            <field>
              <name>SETENA11</name>
              <description>serial peripheral interface 1 interrupt set-enable bit</description>
              <bitOffset>11</bitOffset>
              <bitWidth>1</bitWidth>
              <access>read-write</access>
              <enumeratedValues>
                <enumeratedValue>
                  <name>0</name>
                  <description>write: no effect; read: serial peripheral interface 1 interrupt disabled</description>
                  <value>#0</value>
                </enumeratedValue>
                <enumeratedValue>
                  <name>1</name>
                  <description>write: enable serial peripheral interface 1 interrupt; read: serial peripheral interface 1 interrupt enabled</description>
                  <value>#1</value>
                </enumeratedValue>
              </enumeratedValues>
            </field>
            <field>
              <name>SETENA12</name>
              <description>UART0 status and error interrupt set-enable bit</description>
              <bitOffset>12</bitOffset>
              <bitWidth>1</bitWidth>
              <access>read-write</access>
              <enumeratedValues>
                <enumeratedValue>
                  <name>0</name>
                  <description>write: no effect; read: UART0 status and error interrupt disabled</description>
                  <value>#0</value>
                </enumeratedValue>
                <enumeratedValue>
                  <name>1</name>
                  <description>write: enable UART0 status and error interrupt; read: UART0 status and error interrupt enabled</description>
                  <value>#1</value>
                </enumeratedValue>
              </enumeratedValues>
            </field>
            <field>
              <name>SETENA13</name>
              <description>UART1 status and error interrupt set-enable bit</description>
              <bitOffset>13</bitOffset>
              <bitWidth>1</bitWidth>
              <access>read-write</access>
              <enumeratedValues>
                <enumeratedValue>
                  <name>0</name>
                  <description>write: no effect; read: UART1 status and error interrupt disabled</description>
                  <value>#0</value>
                </enumeratedValue>
                <enumeratedValue>
                  <name>1</name>
                  <description>write: enable UART1 status and error interrupt; read: UART1 status and error interrupt enabled</description>
                  <value>#1</value>
                </enumeratedValue>
              </enumeratedValues>
            </field>
            <field>
              <name>SETENA14</name>
              <description>UART2 status and error interrupt set-enable bit</description>
              <bitOffset>14</bitOffset>
              <bitWidth>1</bitWidth>
              <access>read-write</access>
              <enumeratedValues>
                <enumeratedValue>
                  <name>0</name>
                  <description>write: no effect; read: UART2 status and error interrupt disabled</description>
                  <value>#0</value>
                </enumeratedValue>
                <enumeratedValue>
                  <name>1</name>
                  <description>write: enable UART2 status and error interrupt; read: UART2 status and error interrupt enabled</description>
                  <value>#1</value>
                </enumeratedValue>
              </enumeratedValues>
            </field>
            <field>
              <name>SETENA15</name>
              <description>Analog-to-digital converter 0 interrupt set-enable bit</description>
              <bitOffset>15</bitOffset>
              <bitWidth>1</bitWidth>
              <access>read-write</access>
              <enumeratedValues>
                <enumeratedValue>
                  <name>0</name>
                  <description>write: no effect; read: Analog-to-digital converter 0 interrupt disabled</description>
                  <value>#0</value>
                </enumeratedValue>
                <enumeratedValue>
                  <name>1</name>
                  <description>write: enable Analog-to-digital converter 0 interrupt; read: Analog-to-digital converter 0 interrupt enabled</description>
                  <value>#1</value>
                </enumeratedValue>
              </enumeratedValues>
            </field>
            <field>
              <name>SETENA16</name>
              <description>Comparator 0 interrupt set-enable bit</description>
              <bitOffset>16</bitOffset>
              <bitWidth>1</bitWidth>
              <access>read-write</access>
              <enumeratedValues>
                <enumeratedValue>
                  <name>0</name>
                  <description>write: no effect; read: Comparator 0 interrupt disabled</description>
                  <value>#0</value>
                </enumeratedValue>
                <enumeratedValue>
                  <name>1</name>
                  <description>write: enable Comparator 0 interrupt; read: Comparator 0 interrupt enabled</description>
                  <value>#1</value>
                </enumeratedValue>
              </enumeratedValues>
            </field>
            <field>
              <name>SETENA17</name>
              <description>Timer PWM module 0 interrupt set-enable bit</description>
              <bitOffset>17</bitOffset>
              <bitWidth>1</bitWidth>
              <access>read-write</access>
              <enumeratedValues>
                <enumeratedValue>
                  <name>0</name>
                  <description>write: no effect; read: Timer PWM module 0 interrupt disabled</description>
                  <value>#0</value>
                </enumeratedValue>
                <enumeratedValue>
                  <name>1</name>
                  <description>write: enable Timer PWM module 0 interrupt; read: Timer PWM module 0 interrupt enabled</description>
                  <value>#1</value>
                </enumeratedValue>
              </enumeratedValues>
            </field>
            <field>
              <name>SETENA18</name>
              <description>Timer PWM module 1 interrupt set-enable bit</description>
              <bitOffset>18</bitOffset>
              <bitWidth>1</bitWidth>
              <access>read-write</access>
              <enumeratedValues>
                <enumeratedValue>
                  <name>0</name>
                  <description>write: no effect; read: Timer PWM module 1 interrupt disabled</description>
                  <value>#0</value>
                </enumeratedValue>
                <enumeratedValue>
                  <name>1</name>
                  <description>write: enable Timer PWM module 1 interrupt; read: Timer PWM module 1 interrupt enabled</description>
                  <value>#1</value>
                </enumeratedValue>
              </enumeratedValues>
            </field>
            <field>
              <name>SETENA19</name>
              <description>Timer PWM module 2 interrupt set-enable bit</description>
              <bitOffset>19</bitOffset>
              <bitWidth>1</bitWidth>
              <access>read-write</access>
              <enumeratedValues>
                <enumeratedValue>
                  <name>0</name>
                  <description>write: no effect; read: Timer PWM module 2 interrupt disabled</description>
                  <value>#0</value>
                </enumeratedValue>
                <enumeratedValue>
                  <name>1</name>
                  <description>write: enable Timer PWM module 2 interrupt; read: Timer PWM module 2 interrupt enabled</description>
                  <value>#1</value>
                </enumeratedValue>
              </enumeratedValues>
            </field>
            <field>
              <name>SETENA20</name>
              <description>real time clock alarm interrupt set-enable bit</description>
              <bitOffset>20</bitOffset>
              <bitWidth>1</bitWidth>
              <access>read-write</access>
              <enumeratedValues>
                <enumeratedValue>
                  <name>0</name>
                  <description>write: no effect; read: real time clock alarm interrupt disabled</description>
                  <value>#0</value>
                </enumeratedValue>
                <enumeratedValue>
                  <name>1</name>
                  <description>write: enable real time clock alarm interrupt; read: real time clock alarm interrupt enabled</description>
                  <value>#1</value>
                </enumeratedValue>
              </enumeratedValues>
            </field>
            <field>
              <name>SETENA21</name>
              <description>real time clock seconds interrupt set-enable bit</description>
              <bitOffset>21</bitOffset>
              <bitWidth>1</bitWidth>
              <access>read-write</access>
              <enumeratedValues>
                <enumeratedValue>
                  <name>0</name>
                  <description>write: no effect; read: real time clock seconds interrupt disabled</description>
                  <value>#0</value>
                </enumeratedValue>
                <enumeratedValue>
                  <name>1</name>
                  <description>write: enable real time clock seconds interrupt; read: real time clock seconds interrupt enabled</description>
                  <value>#1</value>
                </enumeratedValue>
              </enumeratedValues>
            </field>
            <field>
              <name>SETENA22</name>
              <description>periodic interrupt timer all channels interrupt set-enable bit</description>
              <bitOffset>22</bitOffset>
              <bitWidth>1</bitWidth>
              <access>read-write</access>
              <enumeratedValues>
                <enumeratedValue>
                  <name>0</name>
                  <description>write: no effect; read: periodic interrupt timer all channels interrupt disabled</description>
                  <value>#0</value>
                </enumeratedValue>
                <enumeratedValue>
                  <name>1</name>
                  <description>write: enable periodic interrupt timer all channels interrupt; read: periodic interrupt timer all channels interrupt enabled</description>
                  <value>#1</value>
                </enumeratedValue>
              </enumeratedValues>
            </field>
            <field>
              <name>SETENA23</name>
              <description>Reserved iv 39 interrupt set-enable bit</description>
              <bitOffset>23</bitOffset>
              <bitWidth>1</bitWidth>
              <access>read-write</access>
              <enumeratedValues>
                <enumeratedValue>
                  <name>0</name>
                  <description>write: no effect; read: Reserved iv 39 interrupt disabled</description>
                  <value>#0</value>
                </enumeratedValue>
                <enumeratedValue>
                  <name>1</name>
                  <description>write: enable Reserved iv 39 interrupt; read: Reserved iv 39 interrupt enabled</description>
                  <value>#1</value>
                </enumeratedValue>
              </enumeratedValues>
            </field>
            <field>
              <name>SETENA24</name>
              <description>Reserved iv 40 interrupt set-enable bit</description>
              <bitOffset>24</bitOffset>
              <bitWidth>1</bitWidth>
              <access>read-write</access>
              <enumeratedValues>
                <enumeratedValue>
                  <name>0</name>
                  <description>write: no effect; read: Reserved iv 40 interrupt disabled</description>
                  <value>#0</value>
                </enumeratedValue>
                <enumeratedValue>
                  <name>1</name>
                  <description>write: enable Reserved iv 40 interrupt; read: Reserved iv 40 interrupt enabled</description>
                  <value>#1</value>
                </enumeratedValue>
              </enumeratedValues>
            </field>
            <field>
              <name>SETENA25</name>
              <description>digital-to-analog converter 0 interrupt set-enable bit</description>
              <bitOffset>25</bitOffset>
              <bitWidth>1</bitWidth>
              <access>read-write</access>
              <enumeratedValues>
                <enumeratedValue>
                  <name>0</name>
                  <description>write: no effect; read: digital-to-analog converter 0 interrupt disabled</description>
                  <value>#0</value>
                </enumeratedValue>
                <enumeratedValue>
                  <name>1</name>
                  <description>write: enable digital-to-analog converter 0 interrupt; read: digital-to-analog converter 0 interrupt enabled</description>
                  <value>#1</value>
                </enumeratedValue>
              </enumeratedValues>
            </field>
            <field>
              <name>SETENA26</name>
              <description>touch sensing input interrupt set-enable bit</description>
              <bitOffset>26</bitOffset>
              <bitWidth>1</bitWidth>
              <access>read-write</access>
              <enumeratedValues>
                <enumeratedValue>
                  <name>0</name>
                  <description>write: no effect; read: touch sensing input interrupt disabled</description>
                  <value>#0</value>
                </enumeratedValue>
                <enumeratedValue>
                  <name>1</name>
                  <description>write: enable touch sensing input interrupt; read: touch sensing input interrupt enabled</description>
                  <value>#1</value>
                </enumeratedValue>
              </enumeratedValues>
            </field>
            <field>
              <name>SETENA27</name>
              <description>multipurpose clock generator interrupt set-enable bit</description>
              <bitOffset>27</bitOffset>
              <bitWidth>1</bitWidth>
              <access>read-write</access>
              <enumeratedValues>
                <enumeratedValue>
                  <name>0</name>
                  <description>write: no effect; read: multipurpose clock generator interrupt disabled</description>
                  <value>#0</value>
                </enumeratedValue>
                <enumeratedValue>
                  <name>1</name>
                  <description>write: enable multipurpose clock generator interrupt; read: multipurpose clock generator interrupt enabled</description>
                  <value>#1</value>
                </enumeratedValue>
              </enumeratedValues>
            </field>
            <field>
              <name>SETENA28</name>
              <description>Low-Power Timer interrupt set-enable bit</description>
              <bitOffset>28</bitOffset>
              <bitWidth>1</bitWidth>
              <access>read-write</access>
              <enumeratedValues>
                <enumeratedValue>
                  <name>0</name>
                  <description>write: no effect; read: Low-Power Timer interrupt disabled</description>
                  <value>#0</value>
                </enumeratedValue>
                <enumeratedValue>
                  <name>1</name>
                  <description>write: enable Low-Power Timer interrupt; read: Low-Power Timer interrupt enabled</description>
                  <value>#1</value>
                </enumeratedValue>
              </enumeratedValues>
            </field>
            <field>
              <name>SETENA29</name>
              <description>Reserved iv 45 interrupt set-enable bit</description>
              <bitOffset>29</bitOffset>
              <bitWidth>1</bitWidth>
              <access>read-write</access>
              <enumeratedValues>
                <enumeratedValue>
                  <name>0</name>
                  <description>write: no effect; read: Reserved iv 45 interrupt disabled</description>
                  <value>#0</value>
                </enumeratedValue>
                <enumeratedValue>
                  <name>1</name>
                  <description>write: enable Reserved iv 45 interrupt; read: Reserved iv 45 interrupt enabled</description>
                  <value>#1</value>
                </enumeratedValue>
              </enumeratedValues>
            </field>
            <field>
              <name>SETENA30</name>
              <description>PORTA pin detect interrupt set-enable bit</description>
              <bitOffset>30</bitOffset>
              <bitWidth>1</bitWidth>
              <access>read-write</access>
              <enumeratedValues>
                <enumeratedValue>
                  <name>0</name>
                  <description>write: no effect; read: PORTA pin detect interrupt disabled</description>
                  <value>#0</value>
                </enumeratedValue>
                <enumeratedValue>
                  <name>1</name>
                  <description>write: enable PORTA pin detect interrupt; read: PORTA pin detect interrupt enabled</description>
                  <value>#1</value>
                </enumeratedValue>
              </enumeratedValues>
            </field>
            <field>
              <name>SETENA31</name>
              <description>PORTC and PORTD pin detect interrupt set-enable bit</description>
              <bitOffset>31</bitOffset>
              <bitWidth>1</bitWidth>
              <access>read-write</access>
              <enumeratedValues>
                <enumeratedValue>
                  <name>0</name>
                  <description>write: no effect; read: PORTC and PORTD pin detect interrupt disabled</description>
                  <value>#0</value>
                </enumeratedValue>
                <enumeratedValue>
                  <name>1</name>
                  <description>write: enable PORTC and PORTD pin detect interrupt; read: PORTC and PORTD pin detect interrupt enabled</description>
                  <value>#1</value>
                </enumeratedValue>
              </enumeratedValues>
            </field>
          </fields>
        </register>
        <register>
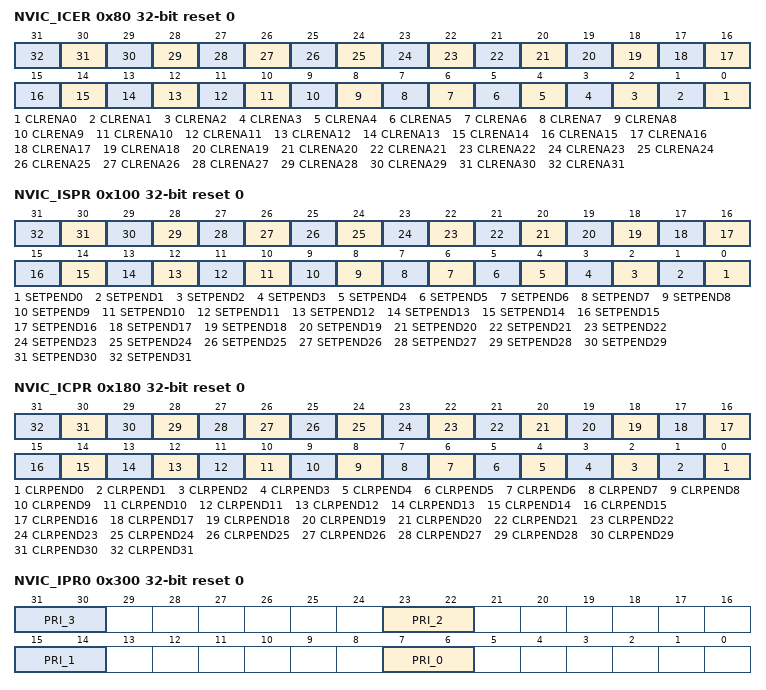
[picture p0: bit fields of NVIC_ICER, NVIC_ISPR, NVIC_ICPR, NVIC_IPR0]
          <name>NVIC_ICER</name>
          <description>Interrupt Clear Enable Register</description>
          <addressOffset>0x80</addressOffset>
          <size>32</size>
          <access>read-write</access>
          <resetValue>0</resetValue>
          <resetMask>0xFFFFFFFF</resetMask>
          <fields>
            <field>
              <name>CLRENA0</name>
              <description>DMA channel 0 transfer complete and error interrupt clear-enable bit</description>
              <bitOffset>0</bitOffset>
              <bitWidth>1</bitWidth>
              <access>read-write</access>
              <enumeratedValues>
                <enumeratedValue>
                  <name>0</name>
                  <description>write: no effect; read: DMA channel 0 transfer complete and error interrupt disabled</description>
                  <value>#0</value>
                </enumeratedValue>
                <enumeratedValue>
                  <name>1</name>
                  <description>write: disable DMA channel 0 transfer complete and error interrupt; read: DMA channel 0 transfer complete and error interrupt enabled</description>
                  <value>#1</value>
                </enumeratedValue>
              </enumeratedValues>
            </field>
            <field>
              <name>CLRENA1</name>
              <description>DMA channel 1 transfer complete and error interrupt clear-enable bit</description>
              <bitOffset>1</bitOffset>
              <bitWidth>1</bitWidth>
              <access>read-write</access>
              <enumeratedValues>
                <enumeratedValue>
                  <name>0</name>
                  <description>write: no effect; read: DMA channel 1 transfer complete and error interrupt disabled</description>
                  <value>#0</value>
                </enumeratedValue>
                <enumeratedValue>
                  <name>1</name>
                  <description>write: disable DMA channel 1 transfer complete and error interrupt; read: DMA channel 1 transfer complete and error interrupt enabled</description>
                  <value>#1</value>
                </enumeratedValue>
              </enumeratedValues>
            </field>
            <field>
              <name>CLRENA2</name>
              <description>DMA channel 2 transfer complete and error interrupt clear-enable bit</description>
              <bitOffset>2</bitOffset>
              <bitWidth>1</bitWidth>
              <access>read-write</access>
              <enumeratedValues>
                <enumeratedValue>
                  <name>0</name>
                  <description>write: no effect; read: DMA channel 2 transfer complete and error interrupt disabled</description>
                  <value>#0</value>
                </enumeratedValue>
                <enumeratedValue>
                  <name>1</name>
                  <description>write: disable DMA channel 2 transfer complete and error interrupt; read: DMA channel 2 transfer complete and error interrupt enabled</description>
                  <value>#1</value>
                </enumeratedValue>
              </enumeratedValues>
            </field>
            <field>
              <name>CLRENA3</name>
              <description>DMA channel 3 transfer complete and error interrupt clear-enable bit</description>
              <bitOffset>3</bitOffset>
              <bitWidth>1</bitWidth>
              <access>read-write</access>
              <enumeratedValues>
                <enumeratedValue>
                  <name>0</name>
                  <description>write: no effect; read: DMA channel 3 transfer complete and error interrupt disabled</description>
                  <value>#0</value>
                </enumeratedValue>
                <enumeratedValue>
                  <name>1</name>
                  <description>write: disable DMA channel 3 transfer complete and error interrupt; read: DMA channel 3 transfer complete and error interrupt enabled</description>
                  <value>#1</value>
                </enumeratedValue>
              </enumeratedValues>
            </field>
            <field>
              <name>CLRENA4</name>
              <description>Reserved iv 20 interrupt clear-enable bit</description>
              <bitOffset>4</bitOffset>
              <bitWidth>1</bitWidth>
              <access>read-write</access>
              <enumeratedValues>
                <enumeratedValue>
                  <name>0</name>
                  <description>write: no effect; read: Reserved iv 20 interrupt disabled</description>
                  <value>#0</value>
                </enumeratedValue>
                <enumeratedValue>
                  <name>1</name>
                  <description>write: disable Reserved iv 20 interrupt; read: Reserved iv 20 interrupt enabled</description>
                  <value>#1</value>
                </enumeratedValue>
              </enumeratedValues>
            </field>
            <field>
              <name>CLRENA5</name>
              <description>FTFA command complete and read collision interrupt clear-enable bit</description>
              <bitOffset>5</bitOffset>
              <bitWidth>1</bitWidth>
              <access>read-write</access>
              <enumeratedValues>
                <enumeratedValue>
                  <name>0</name>
                  <description>write: no effect; read: FTFA command complete and read collision interrupt disabled</description>
                  <value>#0</value>
                </enumeratedValue>
                <enumeratedValue>
                  <name>1</name>
                  <description>write: disable FTFA command complete and read collision interrupt; read: FTFA command complete and read collision interrupt enabled</description>
                  <value>#1</value>
                </enumeratedValue>
              </enumeratedValues>
            </field>
            <field>
              <name>CLRENA6</name>
              <description>low-voltage detect and low-voltage warning interrupt clear-enable bit</description>
              <bitOffset>6</bitOffset>
              <bitWidth>1</bitWidth>
              <access>read-write</access>
              <enumeratedValues>
                <enumeratedValue>
                  <name>0</name>
                  <description>write: no effect; read: low-voltage detect and low-voltage warning interrupt disabled</description>
                  <value>#0</value>
                </enumeratedValue>
                <enumeratedValue>
                  <name>1</name>
                  <description>write: disable low-voltage detect and low-voltage warning interrupt; read: low-voltage detect and low-voltage warning interrupt enabled</description>
                  <value>#1</value>
                </enumeratedValue>
              </enumeratedValues>
            </field>
            <field>
              <name>CLRENA7</name>
              <description>low leakage wakeup interrupt clear-enable bit</description>
              <bitOffset>7</bitOffset>
              <bitWidth>1</bitWidth>
              <access>read-write</access>
              <enumeratedValues>
                <enumeratedValue>
                  <name>0</name>
                  <description>write: no effect; read: low leakage wakeup interrupt disabled</description>
                  <value>#0</value>
                </enumeratedValue>
                <enumeratedValue>
                  <name>1</name>
                  <description>write: disable low leakage wakeup interrupt; read: low leakage wakeup interrupt enabled</description>
                  <value>#1</value>
                </enumeratedValue>
              </enumeratedValues>
            </field>
            <field>
              <name>CLRENA8</name>
              <description>inter-integrated circuit 0 interrupt clear-enable bit</description>
              <bitOffset>8</bitOffset>
              <bitWidth>1</bitWidth>
              <access>read-write</access>
              <enumeratedValues>
                <enumeratedValue>
                  <name>0</name>
                  <description>write: no effect; read: inter-integrated circuit 0 interrupt disabled</description>
                  <value>#0</value>
                </enumeratedValue>
                <enumeratedValue>
                  <name>1</name>
                  <description>write: disable inter-integrated circuit 0 interrupt; read: inter-integrated circuit 0 interrupt enabled</description>
                  <value>#1</value>
                </enumeratedValue>
              </enumeratedValues>
            </field>
            <field>
              <name>CLRENA9</name>
              <description>inter-integrated circuit 1 interrupt clear-enable bit</description>
              <bitOffset>9</bitOffset>
              <bitWidth>1</bitWidth>
              <access>read-write</access>
              <enumeratedValues>
                <enumeratedValue>
                  <name>0</name>
                  <description>write: no effect; read: inter-integrated circuit 1 interrupt disabled</description>
                  <value>#0</value>
                </enumeratedValue>
                <enumeratedValue>
                  <name>1</name>
                  <description>write: disable inter-integrated circuit 1 interrupt; read: inter-integrated circuit 1 interrupt enabled</description>
                  <value>#1</value>
                </enumeratedValue>
              </enumeratedValues>
            </field>
            <field>
              <name>CLRENA10</name>
              <description>serial peripheral interface 0 interrupt clear-enable bit</description>
              <bitOffset>10</bitOffset>
              <bitWidth>1</bitWidth>
              <access>read-write</access>
              <enumeratedValues>
                <enumeratedValue>
                  <name>0</name>
                  <description>write: no effect; read: serial peripheral interface 0 interrupt disabled</description>
                  <value>#0</value>
                </enumeratedValue>
                <enumeratedValue>
                  <name>1</name>
                  <description>write: disable serial peripheral interface 0 interrupt; read: serial peripheral interface 0 interrupt enabled</description>
                  <value>#1</value>
                </enumeratedValue>
              </enumeratedValues>
            </field>
            <field>
              <name>CLRENA11</name>
              <description>serial peripheral interface 1 interrupt clear-enable bit</description>
              <bitOffset>11</bitOffset>
              <bitWidth>1</bitWidth>
              <access>read-write</access>
              <enumeratedValues>
                <enumeratedValue>
                  <name>0</name>
                  <description>write: no effect; read: serial peripheral interface 1 interrupt disabled</description>
                  <value>#0</value>
                </enumeratedValue>
                <enumeratedValue>
                  <name>1</name>
                  <description>write: disable serial peripheral interface 1 interrupt; read: serial peripheral interface 1 interrupt enabled</description>
                  <value>#1</value>
                </enumeratedValue>
              </enumeratedValues>
            </field>
            <field>
              <name>CLRENA12</name>
              <description>UART0 status and error interrupt clear-enable bit</description>
              <bitOffset>12</bitOffset>
              <bitWidth>1</bitWidth>
              <access>read-write</access>
              <enumeratedValues>
                <enumeratedValue>
                  <name>0</name>
                  <description>write: no effect; read: UART0 status and error interrupt disabled</description>
                  <value>#0</value>
                </enumeratedValue>
                <enumeratedValue>
                  <name>1</name>
                  <description>write: disable UART0 status and error interrupt; read: UART0 status and error interrupt enabled</description>
                  <value>#1</value>
                </enumeratedValue>
              </enumeratedValues>
            </field>
            <field>
              <name>CLRENA13</name>
              <description>UART1 status and error interrupt clear-enable bit</description>
              <bitOffset>13</bitOffset>
              <bitWidth>1</bitWidth>
              <access>read-write</access>
              <enumeratedValues>
                <enumeratedValue>
                  <name>0</name>
                  <description>write: no effect; read: UART1 status and error interrupt disabled</description>
                  <value>#0</value>
                </enumeratedValue>
                <enumeratedValue>
                  <name>1</name>
                  <description>write: disable UART1 status and error interrupt; read: UART1 status and error interrupt enabled</description>
                  <value>#1</value>
                </enumeratedValue>
              </enumeratedValues>
            </field>
            <field>
              <name>CLRENA14</name>
              <description>UART2 status and error interrupt clear-enable bit</description>
              <bitOffset>14</bitOffset>
              <bitWidth>1</bitWidth>
              <access>read-write</access>
              <enumeratedValues>
                <enumeratedValue>
                  <name>0</name>
                  <description>write: no effect; read: UART2 status and error interrupt disabled</description>
                  <value>#0</value>
                </enumeratedValue>
                <enumeratedValue>
                  <name>1</name>
                  <description>write: disable UART2 status and error interrupt; read: UART2 status and error interrupt enabled</description>
                  <value>#1</value>
                </enumeratedValue>
              </enumeratedValues>
            </field>
            <field>
              <name>CLRENA15</name>
              <description>Analog-to-digital converter 0 interrupt clear-enable bit</description>
              <bitOffset>15</bitOffset>
              <bitWidth>1</bitWidth>
              <access>read-write</access>
              <enumeratedValues>
                <enumeratedValue>
                  <name>0</name>
                  <description>write: no effect; read: Analog-to-digital converter 0 interrupt disabled</description>
                  <value>#0</value>
                </enumeratedValue>
                <enumeratedValue>
                  <name>1</name>
                  <description>write: disable Analog-to-digital converter 0 interrupt; read: Analog-to-digital converter 0 interrupt enabled</description>
                  <value>#1</value>
                </enumeratedValue>
              </enumeratedValues>
            </field>
            <field>
              <name>CLRENA16</name>
              <description>Comparator 0 interrupt clear-enable bit</description>
              <bitOffset>16</bitOffset>
              <bitWidth>1</bitWidth>
              <access>read-write</access>
              <enumeratedValues>
                <enumeratedValue>
                  <name>0</name>
                  <description>write: no effect; read: Comparator 0 interrupt disabled</description>
                  <value>#0</value>
                </enumeratedValue>
                <enumeratedValue>
                  <name>1</name>
                  <description>write: disable Comparator 0 interrupt; read: Comparator 0 interrupt enabled</description>
                  <value>#1</value>
                </enumeratedValue>
              </enumeratedValues>
            </field>
            <field>
              <name>CLRENA17</name>
              <description>Timer PWM module 0 interrupt clear-enable bit</description>
              <bitOffset>17</bitOffset>
              <bitWidth>1</bitWidth>
              <access>read-write</access>
              <enumeratedValues>
                <enumeratedValue>
                  <name>0</name>
                  <description>write: no effect; read: Timer PWM module 0 interrupt disabled</description>
                  <value>#0</value>
                </enumeratedValue>
                <enumeratedValue>
                  <name>1</name>
                  <description>write: disable Timer PWM module 0 interrupt; read: Timer PWM module 0 interrupt enabled</description>
                  <value>#1</value>
                </enumeratedValue>
              </enumeratedValues>
            </field>
            <field>
              <name>CLRENA18</name>
              <description>Timer PWM module 1 interrupt clear-enable bit</description>
              <bitOffset>18</bitOffset>
              <bitWidth>1</bitWidth>
              <access>read-write</access>
              <enumeratedValues>
                <enumeratedValue>
                  <name>0</name>
                  <description>write: no effect; read: Timer PWM module 1 interrupt disabled</description>
                  <value>#0</value>
                </enumeratedValue>
                <enumeratedValue>
                  <name>1</name>
                  <description>write: disable Timer PWM module 1 interrupt; read: Timer PWM module 1 interrupt enabled</description>
                  <value>#1</value>
                </enumeratedValue>
              </enumeratedValues>
            </field>
            <field>
              <name>CLRENA19</name>
              <description>Timer PWM module 2 interrupt clear-enable bit</description>
              <bitOffset>19</bitOffset>
              <bitWidth>1</bitWidth>
              <access>read-write</access>
              <enumeratedValues>
                <enumeratedValue>
                  <name>0</name>
                  <description>write: no effect; read: Timer PWM module 2 interrupt disabled</description>
                  <value>#0</value>
                </enumeratedValue>
                <enumeratedValue>
                  <name>1</name>
                  <description>write: disable Timer PWM module 2 interrupt; read: Timer PWM module 2 interrupt enabled</description>
                  <value>#1</value>
                </enumeratedValue>
              </enumeratedValues>
            </field>
            <field>
              <name>CLRENA20</name>
              <description>real time clock alarm interrupt clear-enable bit</description>
              <bitOffset>20</bitOffset>
              <bitWidth>1</bitWidth>
              <access>read-write</access>
              <enumeratedValues>
                <enumeratedValue>
                  <name>0</name>
                  <description>write: no effect; read: real time clock alarm interrupt disabled</description>
                  <value>#0</value>
                </enumeratedValue>
                <enumeratedValue>
                  <name>1</name>
                  <description>write: disable real time clock alarm interrupt; read: real time clock alarm interrupt enabled</description>
                  <value>#1</value>
                </enumeratedValue>
              </enumeratedValues>
            </field>
            <field>
              <name>CLRENA21</name>
              <description>real time clock seconds interrupt clear-enable bit</description>
              <bitOffset>21</bitOffset>
              <bitWidth>1</bitWidth>
              <access>read-write</access>
              <enumeratedValues>
                <enumeratedValue>
                  <name>0</name>
                  <description>write: no effect; read: real time clock seconds interrupt disabled</description>
                  <value>#0</value>
                </enumeratedValue>
                <enumeratedValue>
                  <name>1</name>
                  <description>write: disable real time clock seconds interrupt; read: real time clock seconds interrupt enabled</description>
                  <value>#1</value>
                </enumeratedValue>
              </enumeratedValues>
            </field>
            <field>
              <name>CLRENA22</name>
              <description>periodic interrupt timer all channels interrupt clear-enable bit</description>
              <bitOffset>22</bitOffset>
              <bitWidth>1</bitWidth>
              <access>read-write</access>
              <enumeratedValues>
                <enumeratedValue>
                  <name>0</name>
                  <description>write: no effect; read: periodic interrupt timer all channels interrupt disabled</description>
                  <value>#0</value>
                </enumeratedValue>
                <enumeratedValue>
                  <name>1</name>
                  <description>write: disable periodic interrupt timer all channels interrupt; read: periodic interrupt timer all channels interrupt enabled</description>
                  <value>#1</value>
                </enumeratedValue>
              </enumeratedValues>
            </field>
            <field>
              <name>CLRENA23</name>
              <description>Reserved iv 39 interrupt clear-enable bit</description>
              <bitOffset>23</bitOffset>
              <bitWidth>1</bitWidth>
              <access>read-write</access>
              <enumeratedValues>
                <enumeratedValue>
                  <name>0</name>
                  <description>write: no effect; read: Reserved iv 39 interrupt disabled</description>
                  <value>#0</value>
                </enumeratedValue>
                <enumeratedValue>
                  <name>1</name>
                  <description>write: disable Reserved iv 39 interrupt; read: Reserved iv 39 interrupt enabled</description>
                  <value>#1</value>
                </enumeratedValue>
              </enumeratedValues>
            </field>
            <field>
              <name>CLRENA24</name>
              <description>Reserved iv 40 interrupt clear-enable bit</description>
              <bitOffset>24</bitOffset>
              <bitWidth>1</bitWidth>
              <access>read-write</access>
              <enumeratedValues>
                <enumeratedValue>
                  <name>0</name>
                  <description>write: no effect; read: Reserved iv 40 interrupt disabled</description>
                  <value>#0</value>
                </enumeratedValue>
                <enumeratedValue>
                  <name>1</name>
                  <description>write: disable Reserved iv 40 interrupt; read: Reserved iv 40 interrupt enabled</description>
                  <value>#1</value>
                </enumeratedValue>
              </enumeratedValues>
            </field>
            <field>
              <name>CLRENA25</name>
              <description>digital-to-analog converter 0 interrupt clear-enable bit</description>
              <bitOffset>25</bitOffset>
              <bitWidth>1</bitWidth>
              <access>read-write</access>
              <enumeratedValues>
                <enumeratedValue>
                  <name>0</name>
                  <description>write: no effect; read: digital-to-analog converter 0 interrupt disabled</description>
                  <value>#0</value>
                </enumeratedValue>
                <enumeratedValue>
                  <name>1</name>
                  <description>write: disable digital-to-analog converter 0 interrupt; read: digital-to-analog converter 0 interrupt enabled</description>
                  <value>#1</value>
                </enumeratedValue>
              </enumeratedValues>
            </field>
            <field>
              <name>CLRENA26</name>
              <description>touch sensing input interrupt clear-enable bit</description>
              <bitOffset>26</bitOffset>
              <bitWidth>1</bitWidth>
              <access>read-write</access>
              <enumeratedValues>
                <enumeratedValue>
                  <name>0</name>
                  <description>write: no effect; read: touch sensing input interrupt disabled</description>
                  <value>#0</value>
                </enumeratedValue>
                <enumeratedValue>
                  <name>1</name>
                  <description>write: disable touch sensing input interrupt; read: touch sensing input interrupt enabled</description>
                  <value>#1</value>
                </enumeratedValue>
              </enumeratedValues>
            </field>
            <field>
              <name>CLRENA27</name>
              <description>multipurpose clock generator interrupt clear-enable bit</description>
              <bitOffset>27</bitOffset>
              <bitWidth>1</bitWidth>
              <access>read-write</access>
              <enumeratedValues>
                <enumeratedValue>
                  <name>0</name>
                  <description>write: no effect; read: multipurpose clock generator interrupt disabled</description>
                  <value>#0</value>
                </enumeratedValue>
                <enumeratedValue>
                  <name>1</name>
                  <description>write: disable multipurpose clock generator interrupt; read: multipurpose clock generator interrupt enabled</description>
                  <value>#1</value>
                </enumeratedValue>
              </enumeratedValues>
            </field>
            <field>
              <name>CLRENA28</name>
              <description>Low-Power Timer interrupt clear-enable bit</description>
              <bitOffset>28</bitOffset>
              <bitWidth>1</bitWidth>
              <access>read-write</access>
              <enumeratedValues>
                <enumeratedValue>
                  <name>0</name>
                  <description>write: no effect; read: Low-Power Timer interrupt disabled</description>
                  <value>#0</value>
                </enumeratedValue>
                <enumeratedValue>
                  <name>1</name>
                  <description>write: disable Low-Power Timer interrupt; read: Low-Power Timer interrupt enabled</description>
                  <value>#1</value>
                </enumeratedValue>
              </enumeratedValues>
            </field>
            <field>
              <name>CLRENA29</name>
              <description>Reserved iv 45 interrupt clear-enable bit</description>
              <bitOffset>29</bitOffset>
              <bitWidth>1</bitWidth>
              <access>read-write</access>
              <enumeratedValues>
                <enumeratedValue>
                  <name>0</name>
                  <description>write: no effect; read: Reserved iv 45 interrupt disabled</description>
                  <value>#0</value>
                </enumeratedValue>
                <enumeratedValue>
                  <name>1</name>
                  <description>write: disable Reserved iv 45 interrupt; read: Reserved iv 45 interrupt enabled</description>
                  <value>#1</value>
                </enumeratedValue>
              </enumeratedValues>
            </field>
            <field>
              <name>CLRENA30</name>
              <description>PORTA pin detect interrupt clear-enable bit</description>
              <bitOffset>30</bitOffset>
              <bitWidth>1</bitWidth>
              <access>read-write</access>
              <enumeratedValues>
                <enumeratedValue>
                  <name>0</name>
                  <description>write: no effect; read: PORTA pin detect interrupt disabled</description>
                  <value>#0</value>
                </enumeratedValue>
                <enumeratedValue>
                  <name>1</name>
                  <description>write: disable PORTA pin detect interrupt; read: PORTA pin detect interrupt enabled</description>
                  <value>#1</value>
                </enumeratedValue>
              </enumeratedValues>
            </field>
            <field>
              <name>CLRENA31</name>
              <description>PORTC and PORTD pin detect interrupt clear-enable bit</description>
              <bitOffset>31</bitOffset>
              <bitWidth>1</bitWidth>
              <access>read-write</access>
              <enumeratedValues>
                <enumeratedValue>
                  <name>0</name>
                  <description>write: no effect; read: PORTC and PORTD pin detect interrupt disabled</description>
                  <value>#0</value>
                </enumeratedValue>
                <enumeratedValue>
                  <name>1</name>
                  <description>write: disable PORTC and PORTD pin detect interrupt; read: PORTC and PORTD pin detect interrupt enabled</description>
                  <value>#1</value>
                </enumeratedValue>
              </enumeratedValues>
            </field>
          </fields>
        </register>
        <register>
          <name>NVIC_ISPR</name>
          <description>Interrupt Set Pending Register</description>
          <addressOffset>0x100</addressOffset>
          <size>32</size>
          <access>read-write</access>
          <resetValue>0</resetValue>
          <resetMask>0xFFFFFFFF</resetMask>
          <fields>
            <field>
              <name>SETPEND0</name>
              <description>DMA channel 0 transfer complete and error interrupt set-pending bit</description>
              <bitOffset>0</bitOffset>
              <bitWidth>1</bitWidth>
              <access>read-write</access>
              <enumeratedValues>
                <enumeratedValue>
                  <name>0</name>
                  <description>write: no effect; read: DMA channel 0 transfer complete and error interrupt is not pending</description>
                  <value>#0</value>
                </enumeratedValue>
                <enumeratedValue>
                  <name>1</name>
                  <description>write: changes the DMA channel 0 transfer complete and error interrupt state to pending; read: DMA channel 0 transfer complete and error interrupt is pending</description>
                  <value>#1</value>
                </enumeratedValue>
              </enumeratedValues>
            </field>
            <field>
              <name>SETPEND1</name>
              <description>DMA channel 1 transfer complete and error interrupt set-pending bit</description>
              <bitOffset>1</bitOffset>
              <bitWidth>1</bitWidth>
              <access>read-write</access>
              <enumeratedValues>
                <enumeratedValue>
                  <name>0</name>
                  <description>write: no effect; read: DMA channel 1 transfer complete and error interrupt is not pending</description>
                  <value>#0</value>
                </enumeratedValue>
                <enumeratedValue>
                  <name>1</name>
                  <description>write: changes the DMA channel 1 transfer complete and error interrupt state to pending; read: DMA channel 1 transfer complete and error interrupt is pending</description>
                  <value>#1</value>
                </enumeratedValue>
              </enumeratedValues>
            </field>
            <field>
              <name>SETPEND2</name>
              <description>DMA channel 2 transfer complete and error interrupt set-pending bit</description>
              <bitOffset>2</bitOffset>
              <bitWidth>1</bitWidth>
              <access>read-write</access>
              <enumeratedValues>
                <enumeratedValue>
                  <name>0</name>
                  <description>write: no effect; read: DMA channel 2 transfer complete and error interrupt is not pending</description>
                  <value>#0</value>
                </enumeratedValue>
                <enumeratedValue>
                  <name>1</name>
                  <description>write: changes the DMA channel 2 transfer complete and error interrupt state to pending; read: DMA channel 2 transfer complete and error interrupt is pending</description>
                  <value>#1</value>
                </enumeratedValue>
              </enumeratedValues>
            </field>
            <field>
              <name>SETPEND3</name>
              <description>DMA channel 3 transfer complete and error interrupt set-pending bit</description>
              <bitOffset>3</bitOffset>
              <bitWidth>1</bitWidth>
              <access>read-write</access>
              <enumeratedValues>
                <enumeratedValue>
                  <name>0</name>
                  <description>write: no effect; read: DMA channel 3 transfer complete and error interrupt is not pending</description>
                  <value>#0</value>
                </enumeratedValue>
                <enumeratedValue>
                  <name>1</name>
                  <description>write: changes the DMA channel 3 transfer complete and error interrupt state to pending; read: DMA channel 3 transfer complete and error interrupt is pending</description>
                  <value>#1</value>
                </enumeratedValue>
              </enumeratedValues>
            </field>
            <field>
              <name>SETPEND4</name>
              <description>Reserved iv 20 interrupt set-pending bit</description>
              <bitOffset>4</bitOffset>
              <bitWidth>1</bitWidth>
              <access>read-write</access>
              <enumeratedValues>
                <enumeratedValue>
                  <name>0</name>
                  <description>write: no effect; read: Reserved iv 20 interrupt is not pending</description>
                  <value>#0</value>
                </enumeratedValue>
                <enumeratedValue>
                  <name>1</name>
                  <description>write: changes the Reserved iv 20 interrupt state to pending; read: Reserved iv 20 interrupt is pending</description>
                  <value>#1</value>
                </enumeratedValue>
              </enumeratedValues>
            </field>
            <field>
              <name>SETPEND5</name>
              <description>FTFA command complete and read collision interrupt set-pending bit</description>
              <bitOffset>5</bitOffset>
              <bitWidth>1</bitWidth>
              <access>read-write</access>
              <enumeratedValues>
                <enumeratedValue>
                  <name>0</name>
                  <description>write: no effect; read: FTFA command complete and read collision interrupt is not pending</description>
                  <value>#0</value>
                </enumeratedValue>
                <enumeratedValue>
                  <name>1</name>
                  <description>write: changes the FTFA command complete and read collision interrupt state to pending; read: FTFA command complete and read collision interrupt is pending</description>
                  <value>#1</value>
                </enumeratedValue>
              </enumeratedValues>
            </field>
            <field>
              <name>SETPEND6</name>
              <description>low-voltage detect and low-voltage warning interrupt set-pending bit</description>
              <bitOffset>6</bitOffset>
              <bitWidth>1</bitWidth>
              <access>read-write</access>
              <enumeratedValues>
                <enumeratedValue>
                  <name>0</name>
                  <description>write: no effect; read: low-voltage detect and low-voltage warning interrupt is not pending</description>
                  <value>#0</value>
                </enumeratedValue>
                <enumeratedValue>
                  <name>1</name>
                  <description>write: changes the low-voltage detect and low-voltage warning interrupt state to pending; read: low-voltage detect and low-voltage warning interrupt is pending</description>
                  <value>#1</value>
                </enumeratedValue>
              </enumeratedValues>
            </field>
            <field>
              <name>SETPEND7</name>
              <description>low leakage wakeup interrupt set-pending bit</description>
              <bitOffset>7</bitOffset>
              <bitWidth>1</bitWidth>
              <access>read-write</access>
              <enumeratedValues>
                <enumeratedValue>
                  <name>0</name>
                  <description>write: no effect; read: low leakage wakeup interrupt is not pending</description>
                  <value>#0</value>
                </enumeratedValue>
                <enumeratedValue>
                  <name>1</name>
                  <description>write: changes the low leakage wakeup interrupt state to pending; read: low leakage wakeup interrupt is pending</description>
                  <value>#1</value>
                </enumeratedValue>
              </enumeratedValues>
            </field>
            <field>
              <name>SETPEND8</name>
              <description>inter-integrated circuit 0 interrupt set-pending bit</description>
              <bitOffset>8</bitOffset>
              <bitWidth>1</bitWidth>
              <access>read-write</access>
              <enumeratedValues>
                <enumeratedValue>
                  <name>0</name>
                  <description>write: no effect; read: inter-integrated circuit 0 interrupt is not pending</description>
                  <value>#0</value>
                </enumeratedValue>
                <enumeratedValue>
                  <name>1</name>
                  <description>write: changes the inter-integrated circuit 0 interrupt state to pending; read: inter-integrated circuit 0 interrupt is pending</description>
                  <value>#1</value>
                </enumeratedValue>
              </enumeratedValues>
            </field>
            <field>
              <name>SETPEND9</name>
              <description>inter-integrated circuit 1 interrupt set-pending bit</description>
              <bitOffset>9</bitOffset>
              <bitWidth>1</bitWidth>
              <access>read-write</access>
              <enumeratedValues>
                <enumeratedValue>
                  <name>0</name>
                  <description>write: no effect; read: inter-integrated circuit 1 interrupt is not pending</description>
                  <value>#0</value>
                </enumeratedValue>
                <enumeratedValue>
                  <name>1</name>
                  <description>write: changes the inter-integrated circuit 1 interrupt state to pending; read: inter-integrated circuit 1 interrupt is pending</description>
                  <value>#1</value>
                </enumeratedValue>
              </enumeratedValues>
            </field>
            <field>
              <name>SETPEND10</name>
              <description>serial peripheral interface 0 interrupt set-pending bit</description>
              <bitOffset>10</bitOffset>
              <bitWidth>1</bitWidth>
              <access>read-write</access>
              <enumeratedValues>
                <enumeratedValue>
                  <name>0</name>
                  <description>write: no effect; read: serial peripheral interface 0 interrupt is not pending</description>
                  <value>#0</value>
                </enumeratedValue>
                <enumeratedValue>
                  <name>1</name>
                  <description>write: changes the serial peripheral interface 0 interrupt state to pending; read: serial peripheral interface 0 interrupt is pending</description>
                  <value>#1</value>
                </enumeratedValue>
              </enumeratedValues>
            </field>
            <field>
              <name>SETPEND11</name>
              <description>serial peripheral interface 1 interrupt set-pending bit</description>
              <bitOffset>11</bitOffset>
              <bitWidth>1</bitWidth>
              <access>read-write</access>
              <enumeratedValues>
                <enumeratedValue>
                  <name>0</name>
                  <description>write: no effect; read: serial peripheral interface 1 interrupt is not pending</description>
                  <value>#0</value>
                </enumeratedValue>
                <enumeratedValue>
                  <name>1</name>
                  <description>write: changes the serial peripheral interface 1 interrupt state to pending; read: serial peripheral interface 1 interrupt is pending</description>
                  <value>#1</value>
                </enumeratedValue>
              </enumeratedValues>
            </field>
            <field>
              <name>SETPEND12</name>
              <description>UART0 status and error interrupt set-pending bit</description>
              <bitOffset>12</bitOffset>
              <bitWidth>1</bitWidth>
              <access>read-write</access>
              <enumeratedValues>
                <enumeratedValue>
                  <name>0</name>
                  <description>write: no effect; read: UART0 status and error interrupt is not pending</description>
                  <value>#0</value>
                </enumeratedValue>
                <enumeratedValue>
                  <name>1</name>
                  <description>write: changes the UART0 status and error interrupt state to pending; read: UART0 status and error interrupt is pending</description>
                  <value>#1</value>
                </enumeratedValue>
              </enumeratedValues>
            </field>
            <field>
              <name>SETPEND13</name>
              <description>UART1 status and error interrupt set-pending bit</description>
              <bitOffset>13</bitOffset>
              <bitWidth>1</bitWidth>
              <access>read-write</access>
              <enumeratedValues>
                <enumeratedValue>
                  <name>0</name>
                  <description>write: no effect; read: UART1 status and error interrupt is not pending</description>
                  <value>#0</value>
                </enumeratedValue>
                <enumeratedValue>
                  <name>1</name>
                  <description>write: changes the UART1 status and error interrupt state to pending; read: UART1 status and error interrupt is pending</description>
                  <value>#1</value>
                </enumeratedValue>
              </enumeratedValues>
            </field>
            <field>
              <name>SETPEND14</name>
              <description>UART2 status and error interrupt set-pending bit</description>
              <bitOffset>14</bitOffset>
              <bitWidth>1</bitWidth>
              <access>read-write</access>
              <enumeratedValues>
                <enumeratedValue>
                  <name>0</name>
                  <description>write: no effect; read: UART2 status and error interrupt is not pending</description>
                  <value>#0</value>
                </enumeratedValue>
                <enumeratedValue>
                  <name>1</name>
                  <description>write: changes the UART2 status and error interrupt state to pending; read: UART2 status and error interrupt is pending</description>
                  <value>#1</value>
                </enumeratedValue>
              </enumeratedValues>
            </field>
            <field>
              <name>SETPEND15</name>
              <description>Analog-to-digital converter 0 interrupt set-pending bit</description>
              <bitOffset>15</bitOffset>
              <bitWidth>1</bitWidth>
              <access>read-write</access>
              <enumeratedValues>
                <enumeratedValue>
                  <name>0</name>
                  <description>write: no effect; read: Analog-to-digital converter 0 interrupt is not pending</description>
                  <value>#0</value>
                </enumeratedValue>
                <enumeratedValue>
                  <name>1</name>
                  <description>write: changes the Analog-to-digital converter 0 interrupt state to pending; read: Analog-to-digital converter 0 interrupt is pending</description>
                  <value>#1</value>
                </enumeratedValue>
              </enumeratedValues>
            </field>
            <field>
              <name>SETPEND16</name>
              <description>Comparator 0 interrupt set-pending bit</description>
              <bitOffset>16</bitOffset>
              <bitWidth>1</bitWidth>
              <access>read-write</access>
              <enumeratedValues>
                <enumeratedValue>
                  <name>0</name>
                  <description>write: no effect; read: Comparator 0 interrupt is not pending</description>
                  <value>#0</value>
                </enumeratedValue>
                <enumeratedValue>
                  <name>1</name>
                  <description>write: changes the Comparator 0 interrupt state to pending; read: Comparator 0 interrupt is pending</description>
                  <value>#1</value>
                </enumeratedValue>
              </enumeratedValues>
            </field>
            <field>
              <name>SETPEND17</name>
              <description>Timer PWM module 0 interrupt set-pending bit</description>
              <bitOffset>17</bitOffset>
              <bitWidth>1</bitWidth>
              <access>read-write</access>
              <enumeratedValues>
                <enumeratedValue>
                  <name>0</name>
                  <description>write: no effect; read: Timer PWM module 0 interrupt is not pending</description>
                  <value>#0</value>
                </enumeratedValue>
                <enumeratedValue>
                  <name>1</name>
                  <description>write: changes the Timer PWM module 0 interrupt state to pending; read: Timer PWM module 0 interrupt is pending</description>
                  <value>#1</value>
                </enumeratedValue>
              </enumeratedValues>
            </field>
            <field>
              <name>SETPEND18</name>
              <description>Timer PWM module 1 interrupt set-pending bit</description>
              <bitOffset>18</bitOffset>
              <bitWidth>1</bitWidth>
              <access>read-write</access>
              <enumeratedValues>
                <enumeratedValue>
                  <name>0</name>
                  <description>write: no effect; read: Timer PWM module 1 interrupt is not pending</description>
                  <value>#0</value>
                </enumeratedValue>
                <enumeratedValue>
                  <name>1</name>
                  <description>write: changes the Timer PWM module 1 interrupt state to pending; read: Timer PWM module 1 interrupt is pending</description>
                  <value>#1</value>
                </enumeratedValue>
              </enumeratedValues>
            </field>
            <field>
              <name>SETPEND19</name>
              <description>Timer PWM module 2 interrupt set-pending bit</description>
              <bitOffset>19</bitOffset>
              <bitWidth>1</bitWidth>
              <access>read-write</access>
              <enumeratedValues>
                <enumeratedValue>
                  <name>0</name>
                  <description>write: no effect; read: Timer PWM module 2 interrupt is not pending</description>
                  <value>#0</value>
                </enumeratedValue>
                <enumeratedValue>
                  <name>1</name>
                  <description>write: changes the Timer PWM module 2 interrupt state to pending; read: Timer PWM module 2 interrupt is pending</description>
                  <value>#1</value>
                </enumeratedValue>
              </enumeratedValues>
            </field>
            <field>
              <name>SETPEND20</name>
              <description>real time clock alarm interrupt set-pending bit</description>
              <bitOffset>20</bitOffset>
              <bitWidth>1</bitWidth>
              <access>read-write</access>
              <enumeratedValues>
                <enumeratedValue>
                  <name>0</name>
                  <description>write: no effect; read: real time clock alarm interrupt is not pending</description>
                  <value>#0</value>
                </enumeratedValue>
                <enumeratedValue>
                  <name>1</name>
                  <description>write: changes the real time clock alarm interrupt state to pending; read: real time clock alarm interrupt is pending</description>
                  <value>#1</value>
                </enumeratedValue>
              </enumeratedValues>
            </field>
            <field>
              <name>SETPEND21</name>
              <description>real time clock seconds interrupt set-pending bit</description>
              <bitOffset>21</bitOffset>
              <bitWidth>1</bitWidth>
              <access>read-write</access>
              <enumeratedValues>
                <enumeratedValue>
                  <name>0</name>
                  <description>write: no effect; read: real time clock seconds interrupt is not pending</description>
                  <value>#0</value>
                </enumeratedValue>
                <enumeratedValue>
                  <name>1</name>
                  <description>write: changes the real time clock seconds interrupt state to pending; read: real time clock seconds interrupt is pending</description>
                  <value>#1</value>
                </enumeratedValue>
              </enumeratedValues>
            </field>
            <field>
              <name>SETPEND22</name>
              <description>periodic interrupt timer all channels interrupt set-pending bit</description>
              <bitOffset>22</bitOffset>
              <bitWidth>1</bitWidth>
              <access>read-write</access>
              <enumeratedValues>
                <enumeratedValue>
                  <name>0</name>
                  <description>write: no effect; read: periodic interrupt timer all channels interrupt is not pending</description>
                  <value>#0</value>
                </enumeratedValue>
                <enumeratedValue>
                  <name>1</name>
                  <description>write: changes the periodic interrupt timer all channels interrupt state to pending; read: periodic interrupt timer all channels interrupt is pending</description>
                  <value>#1</value>
                </enumeratedValue>
              </enumeratedValues>
            </field>
            <field>
              <name>SETPEND23</name>
              <description>Reserved iv 39 interrupt set-pending bit</description>
              <bitOffset>23</bitOffset>
              <bitWidth>1</bitWidth>
              <access>read-write</access>
              <enumeratedValues>
                <enumeratedValue>
                  <name>0</name>
                  <description>write: no effect; read: Reserved iv 39 interrupt is not pending</description>
                  <value>#0</value>
                </enumeratedValue>
                <enumeratedValue>
                  <name>1</name>
                  <description>write: changes the Reserved iv 39 interrupt state to pending; read: Reserved iv 39 interrupt is pending</description>
                  <value>#1</value>
                </enumeratedValue>
              </enumeratedValues>
            </field>
            <field>
              <name>SETPEND24</name>
              <description>Reserved iv 40 interrupt set-pending bit</description>
              <bitOffset>24</bitOffset>
              <bitWidth>1</bitWidth>
              <access>read-write</access>
              <enumeratedValues>
                <enumeratedValue>
                  <name>0</name>
                  <description>write: no effect; read: Reserved iv 40 interrupt is not pending</description>
                  <value>#0</value>
                </enumeratedValue>
                <enumeratedValue>
                  <name>1</name>
                  <description>write: changes the Reserved iv 40 interrupt state to pending; read: Reserved iv 40 interrupt is pending</description>
                  <value>#1</value>
                </enumeratedValue>
              </enumeratedValues>
            </field>
            <field>
              <name>SETPEND25</name>
              <description>digital-to-analog converter 0 interrupt set-pending bit</description>
              <bitOffset>25</bitOffset>
              <bitWidth>1</bitWidth>
              <access>read-write</access>
              <enumeratedValues>
                <enumeratedValue>
                  <name>0</name>
                  <description>write: no effect; read: digital-to-analog converter 0 interrupt is not pending</description>
                  <value>#0</value>
                </enumeratedValue>
                <enumeratedValue>
                  <name>1</name>
                  <description>write: changes the digital-to-analog converter 0 interrupt state to pending; read: digital-to-analog converter 0 interrupt is pending</description>
                  <value>#1</value>
                </enumeratedValue>
              </enumeratedValues>
            </field>
            <field>
              <name>SETPEND26</name>
              <description>touch sensing input interrupt set-pending bit</description>
              <bitOffset>26</bitOffset>
              <bitWidth>1</bitWidth>
              <access>read-write</access>
              <enumeratedValues>
                <enumeratedValue>
                  <name>0</name>
                  <description>write: no effect; read: touch sensing input interrupt is not pending</description>
                  <value>#0</value>
                </enumeratedValue>
                <enumeratedValue>
                  <name>1</name>
                  <description>write: changes the touch sensing input interrupt state to pending; read: touch sensing input interrupt is pending</description>
                  <value>#1</value>
                </enumeratedValue>
              </enumeratedValues>
            </field>
            <field>
              <name>SETPEND27</name>
              <description>multipurpose clock generator interrupt set-pending bit</description>
              <bitOffset>27</bitOffset>
              <bitWidth>1</bitWidth>
              <access>read-write</access>
              <enumeratedValues>
                <enumeratedValue>
                  <name>0</name>
                  <description>write: no effect; read: multipurpose clock generator interrupt is not pending</description>
                  <value>#0</value>
                </enumeratedValue>
                <enumeratedValue>
                  <name>1</name>
                  <description>write: changes the multipurpose clock generator interrupt state to pending; read: multipurpose clock generator interrupt is pending</description>
                  <value>#1</value>
                </enumeratedValue>
              </enumeratedValues>
            </field>
            <field>
              <name>SETPEND28</name>
              <description>Low-Power Timer interrupt set-pending bit</description>
              <bitOffset>28</bitOffset>
              <bitWidth>1</bitWidth>
              <access>read-write</access>
              <enumeratedValues>
                <enumeratedValue>
                  <name>0</name>
                  <description>write: no effect; read: Low-Power Timer interrupt is not pending</description>
                  <value>#0</value>
                </enumeratedValue>
                <enumeratedValue>
                  <name>1</name>
                  <description>write: changes the Low-Power Timer interrupt state to pending; read: Low-Power Timer interrupt is pending</description>
                  <value>#1</value>
                </enumeratedValue>
              </enumeratedValues>
            </field>
            <field>
              <name>SETPEND29</name>
              <description>Reserved iv 45 interrupt set-pending bit</description>
              <bitOffset>29</bitOffset>
              <bitWidth>1</bitWidth>
              <access>read-write</access>
              <enumeratedValues>
                <enumeratedValue>
                  <name>0</name>
                  <description>write: no effect; read: Reserved iv 45 interrupt is not pending</description>
                  <value>#0</value>
                </enumeratedValue>
                <enumeratedValue>
                  <name>1</name>
                  <description>write: changes the Reserved iv 45 interrupt state to pending; read: Reserved iv 45 interrupt is pending</description>
                  <value>#1</value>
                </enumeratedValue>
              </enumeratedValues>
            </field>
            <field>
              <name>SETPEND30</name>
              <description>PORTA pin detect interrupt set-pending bit</description>
              <bitOffset>30</bitOffset>
              <bitWidth>1</bitWidth>
              <access>read-write</access>
              <enumeratedValues>
                <enumeratedValue>
                  <name>0</name>
                  <description>write: no effect; read: PORTA pin detect interrupt is not pending</description>
                  <value>#0</value>
                </enumeratedValue>
                <enumeratedValue>
                  <name>1</name>
                  <description>write: changes the PORTA pin detect interrupt state to pending; read: PORTA pin detect interrupt is pending</description>
                  <value>#1</value>
                </enumeratedValue>
              </enumeratedValues>
            </field>
            <field>
              <name>SETPEND31</name>
              <description>PORTC and PORTD pin detect interrupt set-pending bit</description>
              <bitOffset>31</bitOffset>
              <bitWidth>1</bitWidth>
              <access>read-write</access>
              <enumeratedValues>
                <enumeratedValue>
                  <name>0</name>
                  <description>write: no effect; read: PORTC and PORTD pin detect interrupt is not pending</description>
                  <value>#0</value>
                </enumeratedValue>
                <enumeratedValue>
                  <name>1</name>
                  <description>write: changes the PORTC and PORTD pin detect interrupt state to pending; read: PORTC and PORTD pin detect interrupt is pending</description>
                  <value>#1</value>
                </enumeratedValue>
              </enumeratedValues>
            </field>
          </fields>
        </register>
        <register>
          <name>NVIC_ICPR</name>
          <description>Interrupt Clear Pending Register</description>
          <addressOffset>0x180</addressOffset>
          <size>32</size>
          <access>read-write</access>
          <resetValue>0</resetValue>
          <resetMask>0xFFFFFFFF</resetMask>
          <fields>
            <field>
              <name>CLRPEND0</name>
              <description>DMA channel 0 transfer complete and error interrupt clear-pending bit</description>
              <bitOffset>0</bitOffset>
              <bitWidth>1</bitWidth>
              <access>read-write</access>
              <enumeratedValues>
                <enumeratedValue>
                  <name>0</name>
                  <description>write: no effect; read: DMA channel 0 transfer complete and error interrupt is not pending</description>
                  <value>#0</value>
                </enumeratedValue>
                <enumeratedValue>
                  <name>1</name>
                  <description>write: removes pending state from the DMA channel 0 transfer complete and error interrupt; read: DMA channel 0 transfer complete and error interrupt is pending</description>
                  <value>#1</value>
                </enumeratedValue>
              </enumeratedValues>
            </field>
            <field>
              <name>CLRPEND1</name>
              <description>DMA channel 1 transfer complete and error interrupt clear-pending bit</description>
              <bitOffset>1</bitOffset>
              <bitWidth>1</bitWidth>
              <access>read-write</access>
              <enumeratedValues>
                <enumeratedValue>
                  <name>0</name>
                  <description>write: no effect; read: DMA channel 1 transfer complete and error interrupt is not pending</description>
                  <value>#0</value>
                </enumeratedValue>
                <enumeratedValue>
                  <name>1</name>
                  <description>write: removes pending state from the DMA channel 1 transfer complete and error interrupt; read: DMA channel 1 transfer complete and error interrupt is pending</description>
                  <value>#1</value>
                </enumeratedValue>
              </enumeratedValues>
            </field>
            <field>
              <name>CLRPEND2</name>
              <description>DMA channel 2 transfer complete and error interrupt clear-pending bit</description>
              <bitOffset>2</bitOffset>
              <bitWidth>1</bitWidth>
              <access>read-write</access>
              <enumeratedValues>
                <enumeratedValue>
                  <name>0</name>
                  <description>write: no effect; read: DMA channel 2 transfer complete and error interrupt is not pending</description>
                  <value>#0</value>
                </enumeratedValue>
                <enumeratedValue>
                  <name>1</name>
                  <description>write: removes pending state from the DMA channel 2 transfer complete and error interrupt; read: DMA channel 2 transfer complete and error interrupt is pending</description>
                  <value>#1</value>
                </enumeratedValue>
              </enumeratedValues>
            </field>
            <field>
              <name>CLRPEND3</name>
              <description>DMA channel 3 transfer complete and error interrupt clear-pending bit</description>
              <bitOffset>3</bitOffset>
              <bitWidth>1</bitWidth>
              <access>read-write</access>
              <enumeratedValues>
                <enumeratedValue>
                  <name>0</name>
                  <description>write: no effect; read: DMA channel 3 transfer complete and error interrupt is not pending</description>
                  <value>#0</value>
                </enumeratedValue>
                <enumeratedValue>
                  <name>1</name>
                  <description>write: removes pending state from the DMA channel 3 transfer complete and error interrupt; read: DMA channel 3 transfer complete and error interrupt is pending</description>
                  <value>#1</value>
                </enumeratedValue>
              </enumeratedValues>
            </field>
            <field>
              <name>CLRPEND4</name>
              <description>Reserved iv 20 interrupt clear-pending bit</description>
              <bitOffset>4</bitOffset>
              <bitWidth>1</bitWidth>
              <access>read-write</access>
              <enumeratedValues>
                <enumeratedValue>
                  <name>0</name>
                  <description>write: no effect; read: Reserved iv 20 interrupt is not pending</description>
                  <value>#0</value>
                </enumeratedValue>
                <enumeratedValue>
                  <name>1</name>
                  <description>write: removes pending state from the Reserved iv 20 interrupt; read: Reserved iv 20 interrupt is pending</description>
                  <value>#1</value>
                </enumeratedValue>
              </enumeratedValues>
            </field>
            <field>
              <name>CLRPEND5</name>
              <description>FTFA command complete and read collision interrupt clear-pending bit</description>
              <bitOffset>5</bitOffset>
              <bitWidth>1</bitWidth>
              <access>read-write</access>
              <enumeratedValues>
                <enumeratedValue>
                  <name>0</name>
                  <description>write: no effect; read: FTFA command complete and read collision interrupt is not pending</description>
                  <value>#0</value>
                </enumeratedValue>
                <enumeratedValue>
                  <name>1</name>
                  <description>write: removes pending state from the FTFA command complete and read collision interrupt; read: FTFA command complete and read collision interrupt is pending</description>
                  <value>#1</value>
                </enumeratedValue>
              </enumeratedValues>
            </field>
            <field>
              <name>CLRPEND6</name>
              <description>low-voltage detect and low-voltage warning interrupt clear-pending bit</description>
              <bitOffset>6</bitOffset>
              <bitWidth>1</bitWidth>
              <access>read-write</access>
              <enumeratedValues>
                <enumeratedValue>
                  <name>0</name>
                  <description>write: no effect; read: low-voltage detect and low-voltage warning interrupt is not pending</description>
                  <value>#0</value>
                </enumeratedValue>
                <enumeratedValue>
                  <name>1</name>
                  <description>write: removes pending state from the low-voltage detect and low-voltage warning interrupt; read: low-voltage detect and low-voltage warning interrupt is pending</description>
                  <value>#1</value>
                </enumeratedValue>
              </enumeratedValues>
            </field>
            <field>
              <name>CLRPEND7</name>
              <description>low leakage wakeup interrupt clear-pending bit</description>
              <bitOffset>7</bitOffset>
              <bitWidth>1</bitWidth>
              <access>read-write</access>
              <enumeratedValues>
                <enumeratedValue>
                  <name>0</name>
                  <description>write: no effect; read: low leakage wakeup interrupt is not pending</description>
                  <value>#0</value>
                </enumeratedValue>
                <enumeratedValue>
                  <name>1</name>
                  <description>write: removes pending state from the low leakage wakeup interrupt; read: low leakage wakeup interrupt is pending</description>
                  <value>#1</value>
                </enumeratedValue>
              </enumeratedValues>
            </field>
            <field>
              <name>CLRPEND8</name>
              <description>inter-integrated circuit 0 interrupt clear-pending bit</description>
              <bitOffset>8</bitOffset>
              <bitWidth>1</bitWidth>
              <access>read-write</access>
              <enumeratedValues>
                <enumeratedValue>
                  <name>0</name>
                  <description>write: no effect; read: inter-integrated circuit 0 interrupt is not pending</description>
                  <value>#0</value>
                </enumeratedValue>
                <enumeratedValue>
                  <name>1</name>
                  <description>write: removes pending state from the inter-integrated circuit 0 interrupt; read: inter-integrated circuit 0 interrupt is pending</description>
                  <value>#1</value>
                </enumeratedValue>
              </enumeratedValues>
            </field>
            <field>
              <name>CLRPEND9</name>
              <description>inter-integrated circuit 1 interrupt clear-pending bit</description>
              <bitOffset>9</bitOffset>
              <bitWidth>1</bitWidth>
              <access>read-write</access>
              <enumeratedValues>
                <enumeratedValue>
                  <name>0</name>
                  <description>write: no effect; read: inter-integrated circuit 1 interrupt is not pending</description>
                  <value>#0</value>
                </enumeratedValue>
                <enumeratedValue>
                  <name>1</name>
                  <description>write: removes pending state from the inter-integrated circuit 1 interrupt; read: inter-integrated circuit 1 interrupt is pending</description>
                  <value>#1</value>
                </enumeratedValue>
              </enumeratedValues>
            </field>
            <field>
              <name>CLRPEND10</name>
              <description>serial peripheral interface 0 interrupt clear-pending bit</description>
              <bitOffset>10</bitOffset>
              <bitWidth>1</bitWidth>
              <access>read-write</access>
              <enumeratedValues>
                <enumeratedValue>
                  <name>0</name>
                  <description>write: no effect; read: serial peripheral interface 0 interrupt is not pending</description>
                  <value>#0</value>
                </enumeratedValue>
                <enumeratedValue>
                  <name>1</name>
                  <description>write: removes pending state from the serial peripheral interface 0 interrupt; read: serial peripheral interface 0 interrupt is pending</description>
                  <value>#1</value>
                </enumeratedValue>
              </enumeratedValues>
            </field>
            <field>
              <name>CLRPEND11</name>
              <description>serial peripheral interface 1 interrupt clear-pending bit</description>
              <bitOffset>11</bitOffset>
              <bitWidth>1</bitWidth>
              <access>read-write</access>
              <enumeratedValues>
                <enumeratedValue>
                  <name>0</name>
                  <description>write: no effect; read: serial peripheral interface 1 interrupt is not pending</description>
                  <value>#0</value>
                </enumeratedValue>
                <enumeratedValue>
                  <name>1</name>
                  <description>write: removes pending state from the serial peripheral interface 1 interrupt; read: serial peripheral interface 1 interrupt is pending</description>
                  <value>#1</value>
                </enumeratedValue>
              </enumeratedValues>
            </field>
            <field>
              <name>CLRPEND12</name>
              <description>UART0 status and error interrupt clear-pending bit</description>
              <bitOffset>12</bitOffset>
              <bitWidth>1</bitWidth>
              <access>read-write</access>
              <enumeratedValues>
                <enumeratedValue>
                  <name>0</name>
                  <description>write: no effect; read: UART0 status and error interrupt is not pending</description>
                  <value>#0</value>
                </enumeratedValue>
                <enumeratedValue>
                  <name>1</name>
                  <description>write: removes pending state from the UART0 status and error interrupt; read: UART0 status and error interrupt is pending</description>
                  <value>#1</value>
                </enumeratedValue>
              </enumeratedValues>
            </field>
            <field>
              <name>CLRPEND13</name>
              <description>UART1 status and error interrupt clear-pending bit</description>
              <bitOffset>13</bitOffset>
              <bitWidth>1</bitWidth>
              <access>read-write</access>
              <enumeratedValues>
                <enumeratedValue>
                  <name>0</name>
                  <description>write: no effect; read: UART1 status and error interrupt is not pending</description>
                  <value>#0</value>
                </enumeratedValue>
                <enumeratedValue>
                  <name>1</name>
                  <description>write: removes pending state from the UART1 status and error interrupt; read: UART1 status and error interrupt is pending</description>
                  <value>#1</value>
                </enumeratedValue>
              </enumeratedValues>
            </field>
            <field>
              <name>CLRPEND14</name>
              <description>UART2 status and error interrupt clear-pending bit</description>
              <bitOffset>14</bitOffset>
              <bitWidth>1</bitWidth>
              <access>read-write</access>
              <enumeratedValues>
                <enumeratedValue>
                  <name>0</name>
                  <description>write: no effect; read: UART2 status and error interrupt is not pending</description>
                  <value>#0</value>
                </enumeratedValue>
                <enumeratedValue>
                  <name>1</name>
                  <description>write: removes pending state from the UART2 status and error interrupt; read: UART2 status and error interrupt is pending</description>
                  <value>#1</value>
                </enumeratedValue>
              </enumeratedValues>
            </field>
            <field>
              <name>CLRPEND15</name>
              <description>Analog-to-digital converter 0 interrupt clear-pending bit</description>
              <bitOffset>15</bitOffset>
              <bitWidth>1</bitWidth>
              <access>read-write</access>
              <enumeratedValues>
                <enumeratedValue>
                  <name>0</name>
                  <description>write: no effect; read: Analog-to-digital converter 0 interrupt is not pending</description>
                  <value>#0</value>
                </enumeratedValue>
                <enumeratedValue>
                  <name>1</name>
                  <description>write: removes pending state from the Analog-to-digital converter 0 interrupt; read: Analog-to-digital converter 0 interrupt is pending</description>
                  <value>#1</value>
                </enumeratedValue>
              </enumeratedValues>
            </field>
            <field>
              <name>CLRPEND16</name>
              <description>Comparator 0 interrupt clear-pending bit</description>
              <bitOffset>16</bitOffset>
              <bitWidth>1</bitWidth>
              <access>read-write</access>
              <enumeratedValues>
                <enumeratedValue>
                  <name>0</name>
                  <description>write: no effect; read: Comparator 0 interrupt is not pending</description>
                  <value>#0</value>
                </enumeratedValue>
                <enumeratedValue>
                  <name>1</name>
                  <description>write: removes pending state from the Comparator 0 interrupt; read: Comparator 0 interrupt is pending</description>
                  <value>#1</value>
                </enumeratedValue>
              </enumeratedValues>
            </field>
            <field>
              <name>CLRPEND17</name>
              <description>Timer PWM module 0 interrupt clear-pending bit</description>
              <bitOffset>17</bitOffset>
              <bitWidth>1</bitWidth>
              <access>read-write</access>
              <enumeratedValues>
                <enumeratedValue>
                  <name>0</name>
                  <description>write: no effect; read: Timer PWM module 0 interrupt is not pending</description>
                  <value>#0</value>
                </enumeratedValue>
                <enumeratedValue>
                  <name>1</name>
                  <description>write: removes pending state from the Timer PWM module 0 interrupt; read: Timer PWM module 0 interrupt is pending</description>
                  <value>#1</value>
                </enumeratedValue>
              </enumeratedValues>
            </field>
            <field>
              <name>CLRPEND18</name>
              <description>Timer PWM module 1 interrupt clear-pending bit</description>
              <bitOffset>18</bitOffset>
              <bitWidth>1</bitWidth>
              <access>read-write</access>
              <enumeratedValues>
                <enumeratedValue>
                  <name>0</name>
                  <description>write: no effect; read: Timer PWM module 1 interrupt is not pending</description>
                  <value>#0</value>
                </enumeratedValue>
                <enumeratedValue>
                  <name>1</name>
                  <description>write: removes pending state from the Timer PWM module 1 interrupt; read: Timer PWM module 1 interrupt is pending</description>
                  <value>#1</value>
                </enumeratedValue>
              </enumeratedValues>
            </field>
            <field>
              <name>CLRPEND19</name>
              <description>Timer PWM module 2 interrupt clear-pending bit</description>
              <bitOffset>19</bitOffset>
              <bitWidth>1</bitWidth>
              <access>read-write</access>
              <enumeratedValues>
                <enumeratedValue>
                  <name>0</name>
                  <description>write: no effect; read: Timer PWM module 2 interrupt is not pending</description>
                  <value>#0</value>
                </enumeratedValue>
                <enumeratedValue>
                  <name>1</name>
                  <description>write: removes pending state from the Timer PWM module 2 interrupt; read: Timer PWM module 2 interrupt is pending</description>
                  <value>#1</value>
                </enumeratedValue>
              </enumeratedValues>
            </field>
            <field>
              <name>CLRPEND20</name>
              <description>real time clock alarm interrupt clear-pending bit</description>
              <bitOffset>20</bitOffset>
              <bitWidth>1</bitWidth>
              <access>read-write</access>
              <enumeratedValues>
                <enumeratedValue>
                  <name>0</name>
                  <description>write: no effect; read: real time clock alarm interrupt is not pending</description>
                  <value>#0</value>
                </enumeratedValue>
                <enumeratedValue>
                  <name>1</name>
                  <description>write: removes pending state from the real time clock alarm interrupt; read: real time clock alarm interrupt is pending</description>
                  <value>#1</value>
                </enumeratedValue>
              </enumeratedValues>
            </field>
            <field>
              <name>CLRPEND21</name>
              <description>real time clock seconds interrupt clear-pending bit</description>
              <bitOffset>21</bitOffset>
              <bitWidth>1</bitWidth>
              <access>read-write</access>
              <enumeratedValues>
                <enumeratedValue>
                  <name>0</name>
                  <description>write: no effect; read: real time clock seconds interrupt is not pending</description>
                  <value>#0</value>
                </enumeratedValue>
                <enumeratedValue>
                  <name>1</name>
                  <description>write: removes pending state from the real time clock seconds interrupt; read: real time clock seconds interrupt is pending</description>
                  <value>#1</value>
                </enumeratedValue>
              </enumeratedValues>
            </field>
            <field>
              <name>CLRPEND22</name>
              <description>periodic interrupt timer all channels interrupt clear-pending bit</description>
              <bitOffset>22</bitOffset>
              <bitWidth>1</bitWidth>
              <access>read-write</access>
              <enumeratedValues>
                <enumeratedValue>
                  <name>0</name>
                  <description>write: no effect; read: periodic interrupt timer all channels interrupt is not pending</description>
                  <value>#0</value>
                </enumeratedValue>
                <enumeratedValue>
                  <name>1</name>
                  <description>write: removes pending state from the periodic interrupt timer all channels interrupt; read: periodic interrupt timer all channels interrupt is pending</description>
                  <value>#1</value>
                </enumeratedValue>
              </enumeratedValues>
            </field>
            <field>
              <name>CLRPEND23</name>
              <description>Reserved iv 39 interrupt clear-pending bit</description>
              <bitOffset>23</bitOffset>
              <bitWidth>1</bitWidth>
              <access>read-write</access>
              <enumeratedValues>
                <enumeratedValue>
                  <name>0</name>
                  <description>write: no effect; read: Reserved iv 39 interrupt is not pending</description>
                  <value>#0</value>
                </enumeratedValue>
                <enumeratedValue>
                  <name>1</name>
                  <description>write: removes pending state from the Reserved iv 39 interrupt; read: Reserved iv 39 interrupt is pending</description>
                  <value>#1</value>
                </enumeratedValue>
              </enumeratedValues>
            </field>
            <field>
              <name>CLRPEND24</name>
              <description>Reserved iv 40 interrupt clear-pending bit</description>
              <bitOffset>24</bitOffset>
              <bitWidth>1</bitWidth>
              <access>read-write</access>
              <enumeratedValues>
                <enumeratedValue>
                  <name>0</name>
                  <description>write: no effect; read: Reserved iv 40 interrupt is not pending</description>
                  <value>#0</value>
                </enumeratedValue>
                <enumeratedValue>
                  <name>1</name>
                  <description>write: removes pending state from the Reserved iv 40 interrupt; read: Reserved iv 40 interrupt is pending</description>
                  <value>#1</value>
                </enumeratedValue>
              </enumeratedValues>
            </field>
            <field>
              <name>CLRPEND25</name>
              <description>digital-to-analog converter 0 interrupt clear-pending bit</description>
              <bitOffset>25</bitOffset>
              <bitWidth>1</bitWidth>
              <access>read-write</access>
              <enumeratedValues>
                <enumeratedValue>
                  <name>0</name>
                  <description>write: no effect; read: digital-to-analog converter 0 interrupt is not pending</description>
                  <value>#0</value>
                </enumeratedValue>
                <enumeratedValue>
                  <name>1</name>
                  <description>write: removes pending state from the digital-to-analog converter 0 interrupt; read: digital-to-analog converter 0 interrupt is pending</description>
                  <value>#1</value>
                </enumeratedValue>
              </enumeratedValues>
            </field>
            <field>
              <name>CLRPEND26</name>
              <description>touch sensing input interrupt clear-pending bit</description>
              <bitOffset>26</bitOffset>
              <bitWidth>1</bitWidth>
              <access>read-write</access>
              <enumeratedValues>
                <enumeratedValue>
                  <name>0</name>
                  <description>write: no effect; read: touch sensing input interrupt is not pending</description>
                  <value>#0</value>
                </enumeratedValue>
                <enumeratedValue>
                  <name>1</name>
                  <description>write: removes pending state from the touch sensing input interrupt; read: touch sensing input interrupt is pending</description>
                  <value>#1</value>
                </enumeratedValue>
              </enumeratedValues>
            </field>
            <field>
              <name>CLRPEND27</name>
              <description>multipurpose clock generator interrupt clear-pending bit</description>
              <bitOffset>27</bitOffset>
              <bitWidth>1</bitWidth>
              <access>read-write</access>
              <enumeratedValues>
                <enumeratedValue>
                  <name>0</name>
                  <description>write: no effect; read: multipurpose clock generator interrupt is not pending</description>
                  <value>#0</value>
                </enumeratedValue>
                <enumeratedValue>
                  <name>1</name>
                  <description>write: removes pending state from the multipurpose clock generator interrupt; read: multipurpose clock generator interrupt is pending</description>
                  <value>#1</value>
                </enumeratedValue>
              </enumeratedValues>
            </field>
            <field>
              <name>CLRPEND28</name>
              <description>Low-Power Timer interrupt clear-pending bit</description>
              <bitOffset>28</bitOffset>
              <bitWidth>1</bitWidth>
              <access>read-write</access>
              <enumeratedValues>
                <enumeratedValue>
                  <name>0</name>
                  <description>write: no effect; read: Low-Power Timer interrupt is not pending</description>
                  <value>#0</value>
                </enumeratedValue>
                <enumeratedValue>
                  <name>1</name>
                  <description>write: removes pending state from the Low-Power Timer interrupt; read: Low-Power Timer interrupt is pending</description>
                  <value>#1</value>
                </enumeratedValue>
              </enumeratedValues>
            </field>
            <field>
              <name>CLRPEND29</name>
              <description>Reserved iv 45 interrupt clear-pending bit</description>
              <bitOffset>29</bitOffset>
              <bitWidth>1</bitWidth>
              <access>read-write</access>
              <enumeratedValues>
                <enumeratedValue>
                  <name>0</name>
                  <description>write: no effect; read: Reserved iv 45 interrupt is not pending</description>
                  <value>#0</value>
                </enumeratedValue>
                <enumeratedValue>
                  <name>1</name>
                  <description>write: removes pending state from the Reserved iv 45 interrupt; read: Reserved iv 45 interrupt is pending</description>
                  <value>#1</value>
                </enumeratedValue>
              </enumeratedValues>
            </field>
            <field>
              <name>CLRPEND30</name>
              <description>PORTA pin detect interrupt clear-pending bit</description>
              <bitOffset>30</bitOffset>
              <bitWidth>1</bitWidth>
              <access>read-write</access>
              <enumeratedValues>
                <enumeratedValue>
                  <name>0</name>
                  <description>write: no effect; read: PORTA pin detect interrupt is not pending</description>
                  <value>#0</value>
                </enumeratedValue>
                <enumeratedValue>
                  <name>1</name>
                  <description>write: removes pending state from the PORTA pin detect interrupt; read: PORTA pin detect interrupt is pending</description>
                  <value>#1</value>
                </enumeratedValue>
              </enumeratedValues>
            </field>
            <field>
              <name>CLRPEND31</name>
              <description>PORTC and PORTD pin detect interrupt clear-pending bit</description>
              <bitOffset>31</bitOffset>
              <bitWidth>1</bitWidth>
              <access>read-write</access>
              <enumeratedValues>
                <enumeratedValue>
                  <name>0</name>
                  <description>write: no effect; read: PORTC and PORTD pin detect interrupt is not pending</description>
                  <value>#0</value>
                </enumeratedValue>
                <enumeratedValue>
                  <name>1</name>
                  <description>write: removes pending state from the PORTC and PORTD pin detect interrupt; read: PORTC and PORTD pin detect interrupt is pending</description>
                  <value>#1</value>
                </enumeratedValue>
              </enumeratedValues>
            </field>
          </fields>
        </register>
        <register>
          <name>NVIC_IPR0</name>
          <description>Interrupt Priority Register 0</description>
          <addressOffset>0x300</addressOffset>
          <size>32</size>
          <access>read-write</access>
          <resetValue>0</resetValue>
          <resetMask>0xFFFFFFFF</resetMask>
          <fields>
            <field>
              <name>PRI_0</name>
              <description>Priority of the DMA channel 0 transfer complete and error interrupt</description>
              <bitOffset>6</bitOffset>
              <bitWidth>2</bitWidth>
              <access>read-write</access>
            </field>
            <field>
              <name>PRI_1</name>
              <description>Priority of the DMA channel 1 transfer complete and error interrupt</description>
              <bitOffset>14</bitOffset>
              <bitWidth>2</bitWidth>
              <access>read-write</access>
            </field>
            <field>
              <name>PRI_2</name>
              <description>Priority of the DMA channel 2 transfer complete and error interrupt</description>
              <bitOffset>22</bitOffset>
              <bitWidth>2</bitWidth>
              <access>read-write</access>
            </field>
            <field>
              <name>PRI_3</name>
              <description>Priority of the DMA channel 3 transfer complete and error interrupt</description>
              <bitOffset>30</bitOffset>
              <bitWidth>2</bitWidth>
              <access>read-write</access>
            </field>
          </fields>
        </register>
        <register>
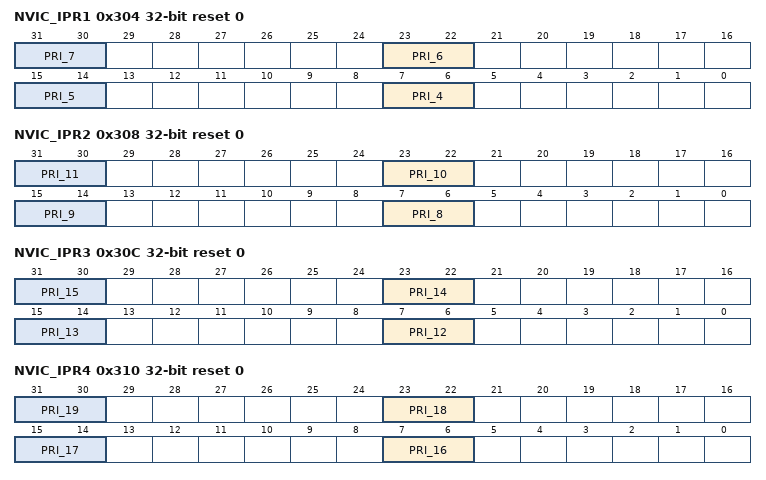
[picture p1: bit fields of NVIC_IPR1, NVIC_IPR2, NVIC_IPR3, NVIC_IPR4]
          <name>NVIC_IPR1</name>
          <description>Interrupt Priority Register 1</description>
          <addressOffset>0x304</addressOffset>
          <size>32</size>
          <access>read-write</access>
          <resetValue>0</resetValue>
          <resetMask>0xFFFFFFFF</resetMask>
          <fields>
            <field>
              <name>PRI_4</name>
              <description>Priority of the Reserved iv 20 interrupt</description>
              <bitOffset>6</bitOffset>
              <bitWidth>2</bitWidth>
              <access>read-write</access>
            </field>
            <field>
              <name>PRI_5</name>
              <description>Priority of the FTFA command complete and read collision interrupt</description>
              <bitOffset>14</bitOffset>
              <bitWidth>2</bitWidth>
              <access>read-write</access>
            </field>
            <field>
              <name>PRI_6</name>
              <description>Priority of the low-voltage detect and low-voltage warning interrupt</description>
              <bitOffset>22</bitOffset>
              <bitWidth>2</bitWidth>
              <access>read-write</access>
            </field>
            <field>
              <name>PRI_7</name>
              <description>Priority of the low leakage wakeup interrupt</description>
              <bitOffset>30</bitOffset>
              <bitWidth>2</bitWidth>
              <access>read-write</access>
            </field>
          </fields>
        </register>
        <register>
          <name>NVIC_IPR2</name>
          <description>Interrupt Priority Register 2</description>
          <addressOffset>0x308</addressOffset>
          <size>32</size>
          <access>read-write</access>
          <resetValue>0</resetValue>
          <resetMask>0xFFFFFFFF</resetMask>
          <fields>
            <field>
              <name>PRI_8</name>
              <description>Priority of the inter-integrated circuit 0 interrupt</description>
              <bitOffset>6</bitOffset>
              <bitWidth>2</bitWidth>
              <access>read-write</access>
            </field>
            <field>
              <name>PRI_9</name>
              <description>Priority of the inter-integrated circuit 1 interrupt</description>
              <bitOffset>14</bitOffset>
              <bitWidth>2</bitWidth>
              <access>read-write</access>
            </field>
            <field>
              <name>PRI_10</name>
              <description>Priority of the serial peripheral interface 0 interrupt</description>
              <bitOffset>22</bitOffset>
              <bitWidth>2</bitWidth>
              <access>read-write</access>
            </field>
            <field>
              <name>PRI_11</name>
              <description>Priority of the serial peripheral interface 1 interrupt</description>
              <bitOffset>30</bitOffset>
              <bitWidth>2</bitWidth>
              <access>read-write</access>
            </field>
          </fields>
        </register>
        <register>
          <name>NVIC_IPR3</name>
          <description>Interrupt Priority Register 3</description>
          <addressOffset>0x30C</addressOffset>
          <size>32</size>
          <access>read-write</access>
          <resetValue>0</resetValue>
          <resetMask>0xFFFFFFFF</resetMask>
          <fields>
            <field>
              <name>PRI_12</name>
              <description>Priority of the UART0 status and error interrupt</description>
              <bitOffset>6</bitOffset>
              <bitWidth>2</bitWidth>
              <access>read-write</access>
            </field>
            <field>
              <name>PRI_13</name>
              <description>Priority of the UART1 status and error interrupt</description>
              <bitOffset>14</bitOffset>
              <bitWidth>2</bitWidth>
              <access>read-write</access>
            </field>
            <field>
              <name>PRI_14</name>
              <description>Priority of the UART2 status and error interrupt</description>
              <bitOffset>22</bitOffset>
              <bitWidth>2</bitWidth>
              <access>read-write</access>
            </field>
            <field>
              <name>PRI_15</name>
              <description>Priority of the Analog-to-digital converter 0 interrupt</description>
              <bitOffset>30</bitOffset>
              <bitWidth>2</bitWidth>
              <access>read-write</access>
            </field>
          </fields>
        </register>
        <register>
          <name>NVIC_IPR4</name>
          <description>Interrupt Priority Register 4</description>
          <addressOffset>0x310</addressOffset>
          <size>32</size>
          <access>read-write</access>
          <resetValue>0</resetValue>
          <resetMask>0xFFFFFFFF</resetMask>
          <fields>
            <field>
              <name>PRI_16</name>
              <description>Priority of the Comparator 0 interrupt</description>
              <bitOffset>6</bitOffset>
              <bitWidth>2</bitWidth>
              <access>read-write</access>
            </field>
            <field>
              <name>PRI_17</name>
              <description>Priority of the Timer PWM module 0 interrupt</description>
              <bitOffset>14</bitOffset>
              <bitWidth>2</bitWidth>
              <access>read-write</access>
            </field>
            <field>
              <name>PRI_18</name>
              <description>Priority of the Timer PWM module 1 interrupt</description>
              <bitOffset>22</bitOffset>
              <bitWidth>2</bitWidth>
              <access>read-write</access>
            </field>
            <field>
              <name>PRI_19</name>
              <description>Priority of the Timer PWM module 2 interrupt</description>
              <bitOffset>30</bitOffset>
              <bitWidth>2</bitWidth>
              <access>read-write</access>
            </field>
          </fields>
        </register>
        <register>
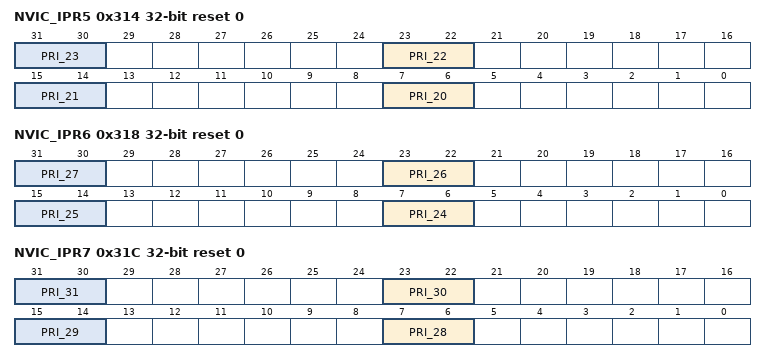
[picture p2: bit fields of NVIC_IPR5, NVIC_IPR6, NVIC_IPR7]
          <name>NVIC_IPR5</name>
          <description>Interrupt Priority Register 5</description>
          <addressOffset>0x314</addressOffset>
          <size>32</size>
          <access>read-write</access>
          <resetValue>0</resetValue>
          <resetMask>0xFFFFFFFF</resetMask>
          <fields>
            <field>
              <name>PRI_20</name>
              <description>Priority of the real time clock alarm interrupt</description>
              <bitOffset>6</bitOffset>
              <bitWidth>2</bitWidth>
              <access>read-write</access>
            </field>
            <field>
              <name>PRI_21</name>
              <description>Priority of the real time clock seconds interrupt</description>
              <bitOffset>14</bitOffset>
              <bitWidth>2</bitWidth>
              <access>read-write</access>
            </field>
            <field>
              <name>PRI_22</name>
              <description>Priority of the periodic interrupt timer all channels interrupt</description>
              <bitOffset>22</bitOffset>
              <bitWidth>2</bitWidth>
              <access>read-write</access>
            </field>
            <field>
              <name>PRI_23</name>
              <description>Priority of the Reserved iv 39 interrupt</description>
              <bitOffset>30</bitOffset>
              <bitWidth>2</bitWidth>
              <access>read-write</access>
            </field>
          </fields>
        </register>
        <register>
          <name>NVIC_IPR6</name>
          <description>Interrupt Priority Register 6</description>
          <addressOffset>0x318</addressOffset>
          <size>32</size>
          <access>read-write</access>
          <resetValue>0</resetValue>
          <resetMask>0xFFFFFFFF</resetMask>
          <fields>
            <field>
              <name>PRI_24</name>
              <description>Priority of the Reserved iv 40 interrupt</description>
              <bitOffset>6</bitOffset>
              <bitWidth>2</bitWidth>
              <access>read-write</access>
            </field>
            <field>
              <name>PRI_25</name>
              <description>Priority of the digital-to-analog converter 0 interrupt</description>
              <bitOffset>14</bitOffset>
              <bitWidth>2</bitWidth>
              <access>read-write</access>
            </field>
            <field>
              <name>PRI_26</name>
              <description>Priority of the touch sensing input interrupt</description>
              <bitOffset>22</bitOffset>
              <bitWidth>2</bitWidth>
              <access>read-write</access>
            </field>
            <field>
              <name>PRI_27</name>
              <description>Priority of the multipurpose clock generator interrupt</description>
              <bitOffset>30</bitOffset>
              <bitWidth>2</bitWidth>
              <access>read-write</access>
            </field>
          </fields>
        </register>
        <register>
          <name>NVIC_IPR7</name>
          <description>Interrupt Priority Register 7</description>
          <addressOffset>0x31C</addressOffset>
          <size>32</size>
          <access>read-write</access>
          <resetValue>0</resetValue>
          <resetMask>0xFFFFFFFF</resetMask>
          <fields>
            <field>
              <name>PRI_28</name>
              <description>Priority of the Low-Power Timer interrupt</description>
              <bitOffset>6</bitOffset>
              <bitWidth>2</bitWidth>
              <access>read-write</access>
            </field>
            <field>
              <name>PRI_29</name>
              <description>Priority of the Reserved iv 45 interrupt</description>
              <bitOffset>14</bitOffset>
              <bitWidth>2</bitWidth>
              <access>read-write</access>
            </field>
            <field>
              <name>PRI_30</name>
              <description>Priority of the PORTA pin detect interrupt</description>
              <bitOffset>22</bitOffset>
              <bitWidth>2</bitWidth>
              <access>read-write</access>
            </field>
            <field>
              <name>PRI_31</name>
              <description>Priority of the PORTC and PORTD pin detect interrupt</description>
              <bitOffset>30</bitOffset>
              <bitWidth>2</bitWidth>
              <access>read-write</access>
            </field>
          </fields>
        </register>
      </registers>
    </peripheral>
    <peripheral>
      <name>MTB</name>
      <description>Micro Trace Buffer</description>
      <prependToName>MTB_</prependToName>
      <baseAddress>0xF0000000</baseAddress>
      <addressBlock>
        <offset>0</offset>
        <size>0x1000</size>
        <usage>registers</usage>
      </addressBlock>
      <registers>
        <register>
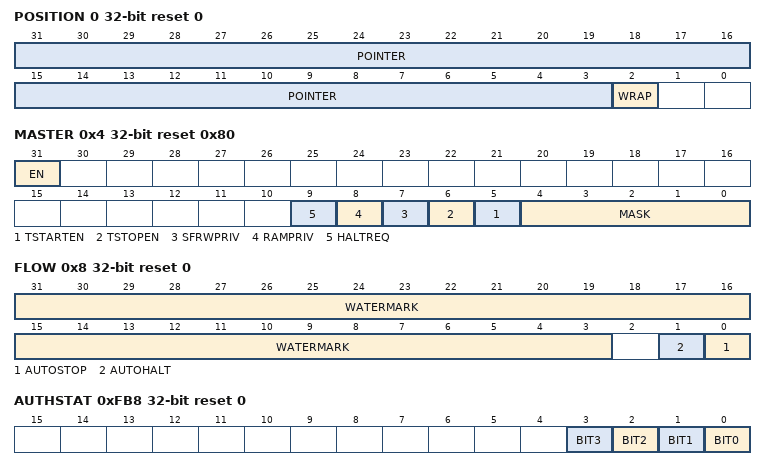
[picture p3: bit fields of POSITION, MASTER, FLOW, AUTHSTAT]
          <name>POSITION</name>
          <description>MTB Position Register</description>
          <addressOffset>0</addressOffset>
          <size>32</size>
          <access>read-write</access>
          <resetValue>0</resetValue>
          <resetMask>0x3</resetMask>
          <fields>
            <field>
              <name>WRAP</name>
              <description>This field is set to 1 automatically when the POINTER value wraps as determined by the MTB_MASTER[MASK] field in the MASTER Trace Control Register</description>
              <bitOffset>2</bitOffset>
              <bitWidth>1</bitWidth>
              <access>read-write</access>
            </field>
            <field>
              <name>POINTER</name>
              <description>Trace Packet Address Pointer[28:0]</description>
              <bitOffset>3</bitOffset>
              <bitWidth>29</bitWidth>
              <access>read-write</access>
            </field>
          </fields>
        </register>
        <register>
          <name>MASTER</name>
          <description>MTB Master Register</description>
          <addressOffset>0x4</addressOffset>
          <size>32</size>
          <access>read-write</access>
          <resetValue>0x80</resetValue>
          <resetMask>0xFFFFFFE0</resetMask>
          <fields>
            <field>
              <name>MASK</name>
              <description>Mask</description>
              <bitOffset>0</bitOffset>
              <bitWidth>5</bitWidth>
              <access>read-write</access>
            </field>
            <field>
              <name>TSTARTEN</name>
              <description>Trace Start Input Enable</description>
              <bitOffset>5</bitOffset>
              <bitWidth>1</bitWidth>
              <access>read-write</access>
            </field>
            <field>
              <name>TSTOPEN</name>
              <description>Trace Stop Input Enable</description>
              <bitOffset>6</bitOffset>
              <bitWidth>1</bitWidth>
              <access>read-write</access>
            </field>
            <field>
              <name>SFRWPRIV</name>
              <description>Special Function Register Write Privilege</description>
              <bitOffset>7</bitOffset>
              <bitWidth>1</bitWidth>
              <access>read-write</access>
            </field>
            <field>
              <name>RAMPRIV</name>
              <description>RAM Privilege</description>
              <bitOffset>8</bitOffset>
              <bitWidth>1</bitWidth>
              <access>read-write</access>
            </field>
            <field>
              <name>HALTREQ</name>
              <description>Halt Request</description>
              <bitOffset>9</bitOffset>
              <bitWidth>1</bitWidth>
              <access>read-write</access>
            </field>
            <field>
              <name>EN</name>
              <description>Main Trace Enable</description>
              <bitOffset>31</bitOffset>
              <bitWidth>1</bitWidth>
              <access>read-write</access>
            </field>
          </fields>
        </register>
        <register>
          <name>FLOW</name>
          <description>MTB Flow Register</description>
          <addressOffset>0x8</addressOffset>
          <size>32</size>
          <access>read-write</access>
          <resetValue>0</resetValue>
          <resetMask>0x4</resetMask>
          <fields>
            <field>
              <name>AUTOSTOP</name>
              <description>If this field is 1 and WATERMARK is equal to MTB_POSITION[POINTER], then MTB_MASTER[EN] is automatically set to 0</description>
              <bitOffset>0</bitOffset>
              <bitWidth>1</bitWidth>
              <access>read-write</access>
            </field>
            <field>
              <name>AUTOHALT</name>
              <description>If this field is 1 and WATERMARK is equal to MTB_POSITION[POINTER], then MTB_MASTER[HALTREQ] is automatically set to 1</description>
              <bitOffset>1</bitOffset>
              <bitWidth>1</bitWidth>
              <access>read-write</access>
            </field>
            <field>
              <name>WATERMARK</name>
              <description>WATERMARK[28:0]</description>
              <bitOffset>3</bitOffset>
              <bitWidth>29</bitWidth>
              <access>read-write</access>
            </field>
          </fields>
        </register>
        <register>
          <name>BASE</name>
          <description>MTB Base Register</description>
          <addressOffset>0xC</addressOffset>
          <size>32</size>
          <access>read-only</access>
          <resetValue>0</resetValue>
          <resetMask>0</resetMask>
          <fields>
            <field>
              <name>BASEADDR</name>
              <description>This value is defined with a hardwired signal and the expression: 0x2000_0000 - (RAM_Size/4)</description>
              <bitOffset>0</bitOffset>
              <bitWidth>32</bitWidth>
              <access>read-only</access>
            </field>
          </fields>
        </register>
        <register>
          <name>MODECTRL</name>
          <description>Integration Mode Control Register</description>
          <addressOffset>0xF00</addressOffset>
          <size>32</size>
          <access>read-only</access>
          <resetValue>0</resetValue>
          <resetMask>0xFFFFFFFF</resetMask>
          <fields>
            <field>
              <name>MODECTRL</name>
              <description>Hardwired to 0x0000_0000</description>
              <bitOffset>0</bitOffset>
              <bitWidth>32</bitWidth>
              <access>read-only</access>
            </field>
          </fields>
        </register>
        <register>
          <name>TAGSET</name>
          <description>Claim TAG Set Register</description>
          <addressOffset>0xFA0</addressOffset>
          <size>32</size>
          <access>read-only</access>
          <resetValue>0</resetValue>
          <resetMask>0xFFFFFFFF</resetMask>
          <fields>
            <field>
              <name>TAGSET</name>
              <description>Hardwired to 0x0000_0000</description>
              <bitOffset>0</bitOffset>
              <bitWidth>32</bitWidth>
              <access>read-only</access>
            </field>
          </fields>
        </register>
        <register>
          <name>TAGCLEAR</name>
          <description>Claim TAG Clear Register</description>
          <addressOffset>0xFA4</addressOffset>
          <size>32</size>
          <access>read-only</access>
          <resetValue>0</resetValue>
          <resetMask>0xFFFFFFFF</resetMask>
          <fields>
            <field>
              <name>TAGCLEAR</name>
              <description>Hardwired to 0x0000_0000</description>
              <bitOffset>0</bitOffset>
              <bitWidth>32</bitWidth>
              <access>read-only</access>
            </field>
          </fields>
        </register>
        <register>
          <name>LOCKACCESS</name>
          <description>Lock Access Register</description>
          <addressOffset>0xFB0</addressOffset>
          <size>32</size>
          <access>read-only</access>
          <resetValue>0</resetValue>
          <resetMask>0xFFFFFFFF</resetMask>
          <fields>
            <field>
              <name>LOCKACCESS</name>
              <description>Hardwired to 0x0000_0000</description>
              <bitOffset>0</bitOffset>
              <bitWidth>32</bitWidth>
              <access>read-only</access>
            </field>
          </fields>
        </register>
        <register>
          <name>LOCKSTAT</name>
          <description>Lock Status Register</description>
          <addressOffset>0xFB4</addressOffset>
          <size>32</size>
          <access>read-only</access>
          <resetValue>0</resetValue>
          <resetMask>0xFFFFFFFF</resetMask>
          <fields>
            <field>
              <name>LOCKSTAT</name>
              <description>Hardwired to 0x0000_0000</description>
              <bitOffset>0</bitOffset>
              <bitWidth>32</bitWidth>
              <access>read-only</access>
            </field>
          </fields>
        </register>
        <register>
          <name>AUTHSTAT</name>
          <description>Authentication Status Register</description>
          <addressOffset>0xFB8</addressOffset>
          <size>32</size>
          <access>read-only</access>
          <resetValue>0</resetValue>
          <resetMask>0xFFFFFFFF</resetMask>
          <fields>
            <field>
              <name>BIT0</name>
              <description>Connected to DBGEN.</description>
              <bitOffset>0</bitOffset>
              <bitWidth>1</bitWidth>
              <access>read-only</access>
            </field>
            <field>
              <name>BIT1</name>
              <description>Hardwired to 1.</description>
              <bitOffset>1</bitOffset>
              <bitWidth>1</bitWidth>
              <access>read-only</access>
            </field>
            <field>
              <name>BIT2</name>
              <description>Connected to NIDEN or DBGEN signal.</description>
              <bitOffset>2</bitOffset>
              <bitWidth>1</bitWidth>
              <access>read-only</access>
            </field>
            <field>
              <name>BIT3</name>
              <description>Hardwired to 1.</description>
              <bitOffset>3</bitOffset>
              <bitWidth>1</bitWidth>
              <access>read-only</access>
            </field>
          </fields>
        </register>
        <register>
          <name>DEVICEARCH</name>
          <description>Device Architecture Register</description>
          <addressOffset>0xFBC</addressOffset>
          <size>32</size>
          <access>read-only</access>
          <resetValue>0x47700A31</resetValue>
          <resetMask>0xFFFFFFFF</resetMask>
          <fields>
            <field>
              <name>DEVICEARCH</name>
              <description>Hardwired to 0x4770_0A31.</description>
              <bitOffset>0</bitOffset>
              <bitWidth>32</bitWidth>
              <access>read-only</access>
            </field>
          </fields>
        </register>
        <register>
          <name>DEVICECFG</name>
          <description>Device Configuration Register</description>
          <addressOffset>0xFC8</addressOffset>
          <size>32</size>
          <access>read-only</access>
          <resetValue>0</resetValue>
          <resetMask>0xFFFFFFFF</resetMask>
          <fields>
            <field>
              <name>DEVICECFG</name>
              <description>Hardwired to 0x0000_0000.</description>
              <bitOffset>0</bitOffset>
              <bitWidth>32</bitWidth>
              <access>read-only</access>
            </field>
          </fields>
        </register>
        <register>
          <name>DEVICETYPID</name>
          <description>Device Type Identifier Register</description>
          <addressOffset>0xFCC</addressOffset>
          <size>32</size>
          <access>read-only</access>
          <resetValue>0x31</resetValue>
          <resetMask>0xFFFFFFFF</resetMask>
          <fields>
            <field>
              <name>DEVICETYPID</name>
              <description>Hardwired to 0x0000_0031.</description>
              <bitOffset>0</bitOffset>
              <bitWidth>32</bitWidth>
              <access>read-only</access>
            </field>
          </fields>
        </register>
        <register>
          <dim>8</dim>
          <dimIncrement>0x4</dimIncrement>
          <dimIndex>4,5,6,7,0,1,2,3</dimIndex>
          <name>PERIPHID%s</name>
          <description>Peripheral ID Register</description>
          <addressOffset>0xFD0</addressOffset>
          <size>32</size>
          <access>read-only</access>
          <resetValue>0</resetValue>
          <resetMask>0</resetMask>
          <fields>
            <field>
              <name>PERIPHID</name>
              <description>Peripheral ID4 is hardwired to 0x0000_0004; ID0 to 0x0000_0032; ID1 to 0x0000_00B9; ID2 to 0x0000_000B; and all the others to 0x0000_0000</description>
              <bitOffset>0</bitOffset>
              <bitWidth>32</bitWidth>
              <access>read-only</access>
            </field>
          </fields>
        </register>
        <register>
          <dim>4</dim>
          <dimIncrement>0x4</dimIncrement>
          <dimIndex>0,1,2,3</dimIndex>
          <name>COMPID%s</name>
          <description>Component ID Register</description>
          <addressOffset>0xFF0</addressOffset>
          <size>32</size>
          <access>read-only</access>
          <resetValue>0</resetValue>
          <resetMask>0</resetMask>
          <fields>
            <field>
              <name>COMPID</name>
              <description>Component ID</description>
              <bitOffset>0</bitOffset>
              <bitWidth>32</bitWidth>
              <access>read-only</access>
            </field>
          </fields>
        </register>
      </registers>
    </peripheral>
    <peripheral>
      <name>MTBDWT</name>
      <description>MTB data watchpoint and trace</description>
      <prependToName>MTBDWT_</prependToName>
      <baseAddress>0xF0001000</baseAddress>
      <addressBlock>
        <offset>0</offset>
        <size>0x1000</size>
        <usage>registers</usage>
      </addressBlock>
      <registers>
        <register>
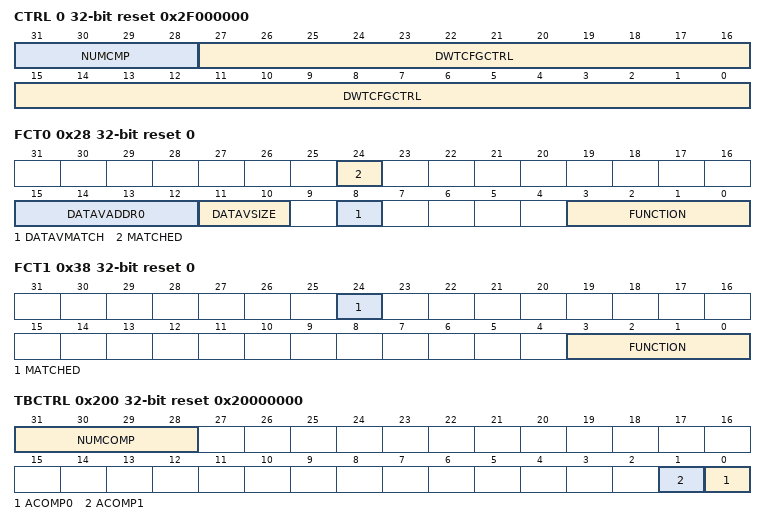
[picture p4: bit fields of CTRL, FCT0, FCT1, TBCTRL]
          <name>CTRL</name>
          <description>MTB DWT Control Register</description>
          <addressOffset>0</addressOffset>
          <size>32</size>
          <access>read-only</access>
          <resetValue>0x2F000000</resetValue>
          <resetMask>0xFFFFFFFF</resetMask>
          <fields>
            <field>
              <name>DWTCFGCTRL</name>
              <description>DWT configuration controls</description>
              <bitOffset>0</bitOffset>
              <bitWidth>28</bitWidth>
              <access>read-only</access>
            </field>
            <field>
              <name>NUMCMP</name>
              <description>Number of comparators</description>
              <bitOffset>28</bitOffset>
              <bitWidth>4</bitWidth>
              <access>read-only</access>
            </field>
          </fields>
        </register>
        <register>
          <dim>2</dim>
          <dimIncrement>0x10</dimIncrement>
          <dimIndex>0,1</dimIndex>
          <name>COMP%s</name>
          <description>MTB_DWT Comparator Register</description>
          <addressOffset>0x20</addressOffset>
          <size>32</size>
          <access>read-write</access>
          <resetValue>0</resetValue>
          <resetMask>0xFFFFFFFF</resetMask>
          <fields>
            <field>
              <name>COMP</name>
              <description>Reference value for comparison</description>
              <bitOffset>0</bitOffset>
              <bitWidth>32</bitWidth>
              <access>read-write</access>
            </field>
          </fields>
        </register>
        <register>
          <dim>2</dim>
          <dimIncrement>0x10</dimIncrement>
          <dimIndex>0,1</dimIndex>
          <name>MASK%s</name>
          <description>MTB_DWT Comparator Mask Register</description>
          <addressOffset>0x24</addressOffset>
          <size>32</size>
          <access>read-write</access>
          <resetValue>0</resetValue>
          <resetMask>0xFFFFFFFF</resetMask>
          <fields>
            <field>
              <name>MASK</name>
              <description>MASK</description>
              <bitOffset>0</bitOffset>
              <bitWidth>5</bitWidth>
              <access>read-write</access>
            </field>
          </fields>
        </register>
        <register>
          <name>FCT0</name>
          <description>MTB_DWT Comparator Function Register 0</description>
          <addressOffset>0x28</addressOffset>
          <size>32</size>
          <access>read-write</access>
          <resetValue>0</resetValue>
          <resetMask>0xFFFFFFFF</resetMask>
          <fields>
            <field>
              <name>FUNCTION</name>
              <description>Function</description>
              <bitOffset>0</bitOffset>
              <bitWidth>4</bitWidth>
              <access>read-write</access>
              <enumeratedValues>
                <enumeratedValue>
                  <name>0000</name>
                  <description>Disabled.</description>
                  <value>#0000</value>
                </enumeratedValue>
                <enumeratedValue>
                  <name>0100</name>
                  <description>Instruction fetch.</description>
                  <value>#0100</value>
                </enumeratedValue>
                <enumeratedValue>
                  <name>0101</name>
                  <description>Data operand read.</description>
                  <value>#0101</value>
                </enumeratedValue>
                <enumeratedValue>
                  <name>0110</name>
                  <description>Data operand write.</description>
                  <value>#0110</value>
                </enumeratedValue>
                <enumeratedValue>
                  <name>0111</name>
                  <description>Data operand (read + write).</description>
                  <value>#0111</value>
                </enumeratedValue>
              </enumeratedValues>
            </field>
            <field>
              <name>DATAVMATCH</name>
              <description>Data Value Match</description>
              <bitOffset>8</bitOffset>
              <bitWidth>1</bitWidth>
              <access>read-write</access>
              <enumeratedValues>
                <enumeratedValue>
                  <name>0</name>
                  <description>Perform address comparison.</description>
                  <value>#0</value>
                </enumeratedValue>
                <enumeratedValue>
                  <name>1</name>
                  <description>Perform data value comparison.</description>
                  <value>#1</value>
                </enumeratedValue>
              </enumeratedValues>
            </field>
            <field>
              <name>DATAVSIZE</name>
              <description>Data Value Size</description>
              <bitOffset>10</bitOffset>
              <bitWidth>2</bitWidth>
              <access>read-write</access>
              <enumeratedValues>
                <enumeratedValue>
                  <name>00</name>
                  <description>Byte.</description>
                  <value>#00</value>
                </enumeratedValue>
                <enumeratedValue>
                  <name>01</name>
                  <description>Halfword.</description>
                  <value>#01</value>
                </enumeratedValue>
                <enumeratedValue>
                  <name>10</name>
                  <description>Word.</description>
                  <value>#10</value>
                </enumeratedValue>
                <enumeratedValue>
                  <name>11</name>
                  <description>Reserved. Any attempts to use this value results in UNPREDICTABLE behavior.</description>
                  <value>#11</value>
                </enumeratedValue>
              </enumeratedValues>
            </field>
            <field>
              <name>DATAVADDR0</name>
              <description>Data Value Address 0</description>
              <bitOffset>12</bitOffset>
              <bitWidth>4</bitWidth>
              <access>read-write</access>
            </field>
            <field>
              <name>MATCHED</name>
              <description>Comparator match</description>
              <bitOffset>24</bitOffset>
              <bitWidth>1</bitWidth>
              <access>read-only</access>
              <enumeratedValues>
                <enumeratedValue>
                  <name>0</name>
                  <description>No match.</description>
                  <value>#0</value>
                </enumeratedValue>
                <enumeratedValue>
                  <name>1</name>
                  <description>Match occurred.</description>
                  <value>#1</value>
                </enumeratedValue>
              </enumeratedValues>
            </field>
          </fields>
        </register>
        <register>
          <name>FCT1</name>
          <description>MTB_DWT Comparator Function Register 1</description>
          <addressOffset>0x38</addressOffset>
          <size>32</size>
          <access>read-write</access>
          <resetValue>0</resetValue>
          <resetMask>0xFFFFFFFF</resetMask>
          <fields>
            <field>
              <name>FUNCTION</name>
              <description>Function</description>
              <bitOffset>0</bitOffset>
              <bitWidth>4</bitWidth>
              <access>read-write</access>
              <enumeratedValues>
                <enumeratedValue>
                  <name>0000</name>
                  <description>Disabled.</description>
                  <value>#0000</value>
                </enumeratedValue>
                <enumeratedValue>
                  <name>0100</name>
                  <description>Instruction fetch.</description>
                  <value>#0100</value>
                </enumeratedValue>
                <enumeratedValue>
                  <name>0101</name>
                  <description>Data operand read.</description>
                  <value>#0101</value>
                </enumeratedValue>
                <enumeratedValue>
                  <name>0110</name>
                  <description>Data operand write.</description>
                  <value>#0110</value>
                </enumeratedValue>
                <enumeratedValue>
                  <name>0111</name>
                  <description>Data operand (read + write).</description>
                  <value>#0111</value>
                </enumeratedValue>
              </enumeratedValues>
            </field>
            <field>
              <name>MATCHED</name>
              <description>Comparator match</description>
              <bitOffset>24</bitOffset>
              <bitWidth>1</bitWidth>
              <access>read-only</access>
              <enumeratedValues>
                <enumeratedValue>
                  <name>0</name>
                  <description>No match.</description>
                  <value>#0</value>
                </enumeratedValue>
                <enumeratedValue>
                  <name>1</name>
                  <description>Match occurred.</description>
                  <value>#1</value>
                </enumeratedValue>
              </enumeratedValues>
            </field>
          </fields>
        </register>
        <register>
          <name>TBCTRL</name>
          <description>MTB_DWT Trace Buffer Control Register</description>
          <addressOffset>0x200</addressOffset>
          <size>32</size>
          <access>read-write</access>
          <resetValue>0x20000000</resetValue>
          <resetMask>0xFFFFFFFF</resetMask>
          <fields>
            <field>
              <name>ACOMP0</name>
              <description>Action based on Comparator 0 match</description>
              <bitOffset>0</bitOffset>
              <bitWidth>1</bitWidth>
              <access>read-write</access>
              <enumeratedValues>
                <enumeratedValue>
                  <name>0</name>
                  <description>Trigger TSTOP based on the assertion of MTBDWT_FCT0[MATCHED].</description>
                  <value>#0</value>
                </enumeratedValue>
                <enumeratedValue>
                  <name>1</name>
                  <description>Trigger TSTART based on the assertion of MTBDWT_FCT0[MATCHED].</description>
                  <value>#1</value>
                </enumeratedValue>
              </enumeratedValues>
            </field>
            <field>
              <name>ACOMP1</name>
              <description>Action based on Comparator 1 match</description>
              <bitOffset>1</bitOffset>
              <bitWidth>1</bitWidth>
              <access>read-write</access>
              <enumeratedValues>
                <enumeratedValue>
                  <name>0</name>
                  <description>Trigger TSTOP based on the assertion of MTBDWT_FCT1[MATCHED].</description>
                  <value>#0</value>
                </enumeratedValue>
                <enumeratedValue>
                  <name>1</name>
                  <description>Trigger TSTART based on the assertion of MTBDWT_FCT1[MATCHED].</description>
                  <value>#1</value>
                </enumeratedValue>
              </enumeratedValues>
            </field>
            <field>
              <name>NUMCOMP</name>
              <description>Number of Comparators</description>
              <bitOffset>28</bitOffset>
              <bitWidth>4</bitWidth>
              <access>read-only</access>
            </field>
          </fields>
        </register>
        <register>
          <name>DEVICECFG</name>
          <description>Device Configuration Register</description>
          <addressOffset>0xFC8</addressOffset>
          <size>32</size>
          <access>read-only</access>
          <resetValue>0</resetValue>
          <resetMask>0xFFFFFFFF</resetMask>
          <fields>
            <field>
              <name>DEVICECFG</name>
              <description>Hardwired to 0x0000_0000.</description>
              <bitOffset>0</bitOffset>
              <bitWidth>32</bitWidth>
              <access>read-only</access>
            </field>
          </fields>
        </register>
        <register>
          <name>DEVICETYPID</name>
          <description>Device Type Identifier Register</description>
          <addressOffset>0xFCC</addressOffset>
          <size>32</size>
          <access>read-only</access>
          <resetValue>0x4</resetValue>
          <resetMask>0xFFFFFFFF</resetMask>
          <fields>
            <field>
              <name>DEVICETYPID</name>
              <description>Hardwired to 0x0000_0004.</description>
              <bitOffset>0</bitOffset>
              <bitWidth>32</bitWidth>
              <access>read-only</access>
            </field>
          </fields>
        </register>
        <register>
          <dim>8</dim>
          <dimIncrement>0x4</dimIncrement>
          <dimIndex>4,5,6,7,0,1,2,3</dimIndex>
          <name>PERIPHID%s</name>
          <description>Peripheral ID Register</description>
          <addressOffset>0xFD0</addressOffset>
          <size>32</size>
          <access>read-only</access>
          <resetValue>0</resetValue>
          <resetMask>0</resetMask>
          <fields>
            <field>
              <name>PERIPHID</name>
              <description>Peripheral ID1 is hardwired to 0x0000_00E0; ID2 to 0x0000_0008; and all the others to 0x0000_0000.</description>
              <bitOffset>0</bitOffset>
              <bitWidth>32</bitWidth>
              <access>read-only</access>
            </field>
          </fields>
        </register>
        <register>
          <dim>4</dim>
          <dimIncrement>0x4</dimIncrement>
          <dimIndex>0,1,2,3</dimIndex>
          <name>COMPID%s</name>
          <description>Component ID Register</description>
          <addressOffset>0xFF0</addressOffset>
          <size>32</size>
          <access>read-only</access>
          <resetValue>0</resetValue>
          <resetMask>0</resetMask>
          <fields>
            <field>
              <name>COMPID</name>
              <description>Component ID</description>
              <bitOffset>0</bitOffset>
              <bitWidth>32</bitWidth>
              <access>read-only</access>
            </field>
          </fields>
        </register>
      </registers>
    </peripheral>
    <peripheral>
      <name>ROM</name>
      <description>System ROM</description>
      <prependToName>ROM_</prependToName>
      <baseAddress>0xF0002000</baseAddress>
      <addressBlock>
        <offset>0</offset>
        <size>0x1000</size>
        <usage>registers</usage>
      </addressBlock>
      <registers>
        <register>
          <dim>3</dim>
          <dimIncrement>0x4</dimIncrement>
          <dimIndex>0,1,2</dimIndex>
          <name>ENTRY%s</name>
          <description>Entry</description>
          <addressOffset>0</addressOffset>
          <size>32</size>
          <access>read-only</access>
          <resetValue>0</resetValue>
          <resetMask>0</resetMask>
          <fields>
            <field>
              <name>ENTRY</name>
              <description>ENTRY</description>
              <bitOffset>0</bitOffset>
              <bitWidth>32</bitWidth>
              <access>read-only</access>
            </field>
          </fields>
        </register>
        <register>
          <name>TABLEMARK</name>
          <description>End of Table Marker Register</description>
          <addressOffset>0xC</addressOffset>
          <size>32</size>
          <access>read-only</access>
          <resetValue>0</resetValue>
          <resetMask>0xFFFFFFFF</resetMask>
          <fields>
            <field>
              <name>MARK</name>
              <description>Hardwired to 0x0000_0000</description>
              <bitOffset>0</bitOffset>
              <bitWidth>32</bitWidth>
              <access>read-only</access>
            </field>
          </fields>
        </register>
        <register>
          <name>SYSACCESS</name>
          <description>System Access Register</description>
          <addressOffset>0xFCC</addressOffset>
          <size>32</size>
          <access>read-only</access>
          <resetValue>0x1</resetValue>
          <resetMask>0xFFFFFFFF</resetMask>
          <fields>
            <field>
              <name>SYSACCESS</name>
              <description>Hardwired to 0x0000_0001</description>
              <bitOffset>0</bitOffset>
              <bitWidth>32</bitWidth>
              <access>read-only</access>
            </field>
          </fields>
        </register>
        <register>
          <dim>8</dim>
          <dimIncrement>0x4</dimIncrement>
          <dimIndex>4,5,6,7,0,1,2,3</dimIndex>
          <name>PERIPHID%s</name>
          <description>Peripheral ID Register</description>
          <addressOffset>0xFD0</addressOffset>
          <size>32</size>
          <access>read-only</access>
          <resetValue>0</resetValue>
          <resetMask>0</resetMask>
          <fields>
            <field>
              <name>PERIPHID</name>
              <description>Peripheral ID1 is hardwired to 0x0000_00E0; ID2 to 0x0000_0008; and all the others to 0x0000_0000.</description>
              <bitOffset>0</bitOffset>
              <bitWidth>32</bitWidth>
              <access>read-only</access>
            </field>
          </fields>
        </register>
        <register>
          <dim>4</dim>
          <dimIncrement>0x4</dimIncrement>
          <dimIndex>0,1,2,3</dimIndex>
          <name>COMPID%s</name>
          <description>Component ID Register</description>
          <addressOffset>0xFF0</addressOffset>
          <size>32</size>
          <access>read-only</access>
          <resetValue>0</resetValue>
          <resetMask>0</resetMask>
          <fields>
            <field>
              <name>COMPID</name>
              <description>Component ID</description>
              <bitOffset>0</bitOffset>
              <bitWidth>32</bitWidth>
              <access>read-only</access>
            </field>
          </fields>
        </register>
      </registers>
    </peripheral>
    <peripheral>
      <name>MCM</name>
      <description>Core Platform Miscellaneous Control Module</description>
      <prependToName>MCM_</prependToName>
      <baseAddress>0xF0003000</baseAddress>
      <addressBlock>
        <offset>0x8</offset>
        <size>0x3C</size>
        <usage>registers</usage>
      </addressBlock>
      <registers>
        <register>
          <name>PLASC</name>
          <description>Crossbar Switch (AXBS) Slave Configuration</description>
          <addressOffset>0x8</addressOffset>
          <size>16</size>
          <access>read-only</access>
          <resetValue>0x7</resetValue>
          <resetMask>0xFFFF</resetMask>
          <fields>
            <field>
              <name>ASC</name>
              <description>Each bit in the ASC field indicates whether there is a corresponding connection to the crossbar switch&apos;s slave input port.</description>
              <bitOffset>0</bitOffset>
              <bitWidth>8</bitWidth>
              <access>read-only</access>
              <enumeratedValues>
                <enumeratedValue>
                  <name>0</name>
                  <description>A bus slave connection to AXBS input port n is absent.</description>
                  <value>#0</value>
                </enumeratedValue>
                <enumeratedValue>
                  <name>1</name>
                  <description>A bus slave connection to AXBS input port n is present.</description>
                  <value>#1</value>
                </enumeratedValue>
              </enumeratedValues>
            </field>
          </fields>
        </register>
        <register>
          <name>PLAMC</name>
          <description>Crossbar Switch (AXBS) Master Configuration</description>
          <addressOffset>0xA</addressOffset>
          <size>16</size>
          <access>read-only</access>
          <resetValue>0xD</resetValue>
          <resetMask>0xFFFF</resetMask>
          <fields>
            <field>
              <name>AMC</name>
              <description>Each bit in the AMC field indicates whether there is a corresponding connection to the AXBS master input port.</description>
              <bitOffset>0</bitOffset>
              <bitWidth>8</bitWidth>
              <access>read-only</access>
              <enumeratedValues>
                <enumeratedValue>
                  <name>0</name>
                  <description>A bus master connection to AXBS input port n is absent</description>
                  <value>#0</value>
                </enumeratedValue>
                <enumeratedValue>
                  <name>1</name>
                  <description>A bus master connection to AXBS input port n is present</description>
                  <value>#1</value>
                </enumeratedValue>
              </enumeratedValues>
            </field>
          </fields>
        </register>
        <register>
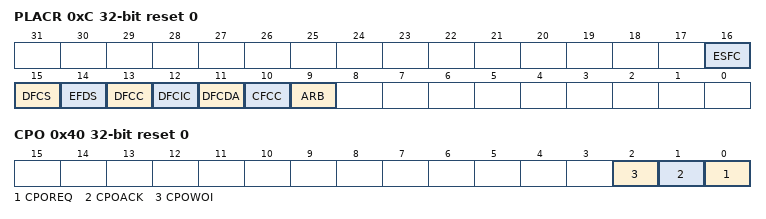
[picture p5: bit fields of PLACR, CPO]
          <name>PLACR</name>
          <description>Platform Control Register</description>
          <addressOffset>0xC</addressOffset>
          <size>32</size>
          <access>read-write</access>
          <resetValue>0</resetValue>
          <resetMask>0xFFFFFFFF</resetMask>
          <fields>
            <field>
              <name>ARB</name>
              <description>Arbitration select</description>
              <bitOffset>9</bitOffset>
              <bitWidth>1</bitWidth>
              <access>read-write</access>
              <enumeratedValues>
                <enumeratedValue>
                  <name>0</name>
                  <description>Fixed-priority arbitration for the crossbar masters</description>
                  <value>#0</value>
                </enumeratedValue>
                <enumeratedValue>
                  <name>1</name>
                  <description>Round-robin arbitration for the crossbar masters</description>
                  <value>#1</value>
                </enumeratedValue>
              </enumeratedValues>
            </field>
            <field>
              <name>CFCC</name>
              <description>Clear Flash Controller Cache</description>
              <bitOffset>10</bitOffset>
              <bitWidth>1</bitWidth>
              <access>write-only</access>
            </field>
            <field>
              <name>DFCDA</name>
              <description>Disable Flash Controller Data Caching</description>
              <bitOffset>11</bitOffset>
              <bitWidth>1</bitWidth>
              <access>read-write</access>
              <enumeratedValues>
                <enumeratedValue>
                  <name>0</name>
                  <description>Enable flash controller data caching</description>
                  <value>#0</value>
                </enumeratedValue>
                <enumeratedValue>
                  <name>1</name>
                  <description>Disable flash controller data caching.</description>
                  <value>#1</value>
                </enumeratedValue>
              </enumeratedValues>
            </field>
            <field>
              <name>DFCIC</name>
              <description>Disable Flash Controller Instruction Caching</description>
              <bitOffset>12</bitOffset>
              <bitWidth>1</bitWidth>
              <access>read-write</access>
              <enumeratedValues>
                <enumeratedValue>
                  <name>0</name>
                  <description>Enable flash controller instruction caching.</description>
                  <value>#0</value>
                </enumeratedValue>
                <enumeratedValue>
                  <name>1</name>
                  <description>Disable flash controller instruction caching.</description>
                  <value>#1</value>
                </enumeratedValue>
              </enumeratedValues>
            </field>
            <field>
              <name>DFCC</name>
              <description>Disable Flash Controller Cache</description>
              <bitOffset>13</bitOffset>
              <bitWidth>1</bitWidth>
              <access>read-write</access>
              <enumeratedValues>
                <enumeratedValue>
                  <name>0</name>
                  <description>Enable flash controller cache.</description>
                  <value>#0</value>
                </enumeratedValue>
                <enumeratedValue>
                  <name>1</name>
                  <description>Disable flash controller cache.</description>
                  <value>#1</value>
                </enumeratedValue>
              </enumeratedValues>
            </field>
            <field>
              <name>EFDS</name>
              <description>Enable Flash Data Speculation</description>
              <bitOffset>14</bitOffset>
              <bitWidth>1</bitWidth>
              <access>read-write</access>
              <enumeratedValues>
                <enumeratedValue>
                  <name>0</name>
                  <description>Disable flash data speculation.</description>
                  <value>#0</value>
                </enumeratedValue>
                <enumeratedValue>
                  <name>1</name>
                  <description>Enable flash data speculation.</description>
                  <value>#1</value>
                </enumeratedValue>
              </enumeratedValues>
            </field>
            <field>
              <name>DFCS</name>
              <description>Disable Flash Controller Speculation</description>
              <bitOffset>15</bitOffset>
              <bitWidth>1</bitWidth>
              <access>read-write</access>
              <enumeratedValues>
                <enumeratedValue>
                  <name>0</name>
                  <description>Enable flash controller speculation.</description>
                  <value>#0</value>
                </enumeratedValue>
                <enumeratedValue>
                  <name>1</name>
                  <description>Disable flash controller speculation.</description>
                  <value>#1</value>
                </enumeratedValue>
              </enumeratedValues>
            </field>
            <field>
              <name>ESFC</name>
              <description>Enable Stalling Flash Controller</description>
              <bitOffset>16</bitOffset>
              <bitWidth>1</bitWidth>
              <access>read-write</access>
              <enumeratedValues>
                <enumeratedValue>
                  <name>0</name>
                  <description>Disable stalling flash controller when flash is busy.</description>
                  <value>#0</value>
                </enumeratedValue>
                <enumeratedValue>
                  <name>1</name>
                  <description>Enable stalling flash controller when flash is busy.</description>
                  <value>#1</value>
                </enumeratedValue>
              </enumeratedValues>
            </field>
          </fields>
        </register>
        <register>
          <name>CPO</name>
          <description>Compute Operation Control Register</description>
          <addressOffset>0x40</addressOffset>
          <size>32</size>
          <access>read-write</access>
          <resetValue>0</resetValue>
          <resetMask>0xFFFFFFFF</resetMask>
          <fields>
            <field>
              <name>CPOREQ</name>
              <description>Compute Operation Request</description>
              <bitOffset>0</bitOffset>
              <bitWidth>1</bitWidth>
              <access>read-write</access>
              <enumeratedValues>
                <enumeratedValue>
                  <name>0</name>
                  <description>Request is cleared.</description>
                  <value>#0</value>
                </enumeratedValue>
                <enumeratedValue>
                  <name>1</name>
                  <description>Request Compute Operation.</description>
                  <value>#1</value>
                </enumeratedValue>
              </enumeratedValues>
            </field>
            <field>
              <name>CPOACK</name>
              <description>Compute Operation Acknowledge</description>
              <bitOffset>1</bitOffset>
              <bitWidth>1</bitWidth>
              <access>read-only</access>
              <enumeratedValues>
                <enumeratedValue>
                  <name>0</name>
                  <description>Compute operation entry has not completed or compute operation exit has completed.</description>
                  <value>#0</value>
                </enumeratedValue>
                <enumeratedValue>
                  <name>1</name>
                  <description>Compute operation entry has completed or compute operation exit has not completed.</description>
                  <value>#1</value>
                </enumeratedValue>
              </enumeratedValues>
            </field>
            <field>
              <name>CPOWOI</name>
              <description>Compute Operation Wake-up on Interrupt</description>
              <bitOffset>2</bitOffset>
              <bitWidth>1</bitWidth>
              <access>read-write</access>
              <enumeratedValues>
                <enumeratedValue>
                  <name>0</name>
                  <description>No effect.</description>
                  <value>#0</value>
                </enumeratedValue>
                <enumeratedValue>
                  <name>1</name>
                  <description>When set, the CPOREQ is cleared on any interrupt or exception vector fetch.</description>
                  <value>#1</value>
                </enumeratedValue>
              </enumeratedValues>
            </field>
          </fields>
        </register>
      </registers>
    </peripheral>
    <peripheral>
      <name>FGPIOA</name>
      <description>General Purpose Input/Output</description>
      <groupName>FGPIO</groupName>
      <prependToName>FGPIOA_</prependToName>
      <baseAddress>0xF8000000</baseAddress>
      <addressBlock>
        <offset>0</offset>
        <size>0x18</size>
        <usage>registers</usage>
      </addressBlock>
      <registers>
        <register>
          <name>PDOR</name>
          <description>Port Data Output Register</description>
          <addressOffset>0</addressOffset>
          <size>32</size>
          <access>read-write</access>
          <resetValue>0</resetValue>
          <resetMask>0xFFFFFFFF</resetMask>
          <fields>
            <field>
              <name>PDO</name>
              <description>Port Data Output</description>
              <bitOffset>0</bitOffset>
              <bitWidth>32</bitWidth>
              <access>read-write</access>
              <enumeratedValues>
                <enumeratedValue>
                  <name>0</name>
                  <description>Logic level 0 is driven on pin, provided pin is configured for general-purpose output.</description>
                  <value>#0</value>
                </enumeratedValue>
                <enumeratedValue>
                  <name>1</name>
                  <description>Logic level 1 is driven on pin, provided pin is configured for general-purpose output.</description>
                  <value>#1</value>
                </enumeratedValue>
              </enumeratedValues>
            </field>
          </fields>
        </register>
        <register>
          <name>PSOR</name>
          <description>Port Set Output Register</description>
          <addressOffset>0x4</addressOffset>
          <size>32</size>
          <access>write-only</access>
          <resetValue>0</resetValue>
          <resetMask>0xFFFFFFFF</resetMask>
          <fields>
            <field>
              <name>PTSO</name>
              <description>Port Set Output</description>
              <bitOffset>0</bitOffset>
              <bitWidth>32</bitWidth>
              <access>write-only</access>
              <enumeratedValues>
                <enumeratedValue>
                  <name>0</name>
                  <description>Corresponding bit in PDORn does not change.</description>
                  <value>#0</value>
                </enumeratedValue>
                <enumeratedValue>
                  <name>1</name>
                  <description>Corresponding bit in PDORn is set to logic 1.</description>
                  <value>#1</value>
                </enumeratedValue>
              </enumeratedValues>
            </field>
          </fields>
        </register>
        <register>
          <name>PCOR</name>
          <description>Port Clear Output Register</description>
          <addressOffset>0x8</addressOffset>
          <size>32</size>
          <access>write-only</access>
          <resetValue>0</resetValue>
          <resetMask>0xFFFFFFFF</resetMask>
          <fields>
            <field>
              <name>PTCO</name>
              <description>Port Clear Output</description>
              <bitOffset>0</bitOffset>
              <bitWidth>32</bitWidth>
              <access>write-only</access>
              <enumeratedValues>
                <enumeratedValue>
                  <name>0</name>
                  <description>Corresponding bit in PDORn does not change.</description>
                  <value>#0</value>
                </enumeratedValue>
                <enumeratedValue>
                  <name>1</name>
                  <description>Corresponding bit in PDORn is cleared to logic 0.</description>
                  <value>#1</value>
                </enumeratedValue>
              </enumeratedValues>
            </field>
          </fields>
        </register>
        <register>
          <name>PTOR</name>
          <description>Port Toggle Output Register</description>
          <addressOffset>0xC</addressOffset>
          <size>32</size>
          <access>write-only</access>
          <resetValue>0</resetValue>
          <resetMask>0xFFFFFFFF</resetMask>
          <fields>
            <field>
              <name>PTTO</name>
              <description>Port Toggle Output</description>
              <bitOffset>0</bitOffset>
              <bitWidth>32</bitWidth>
              <access>write-only</access>
              <enumeratedValues>
                <enumeratedValue>
                  <name>0</name>
                  <description>Corresponding bit in PDORn does not change.</description>
                  <value>#0</value>
                </enumeratedValue>
                <enumeratedValue>
                  <name>1</name>
                  <description>Corresponding bit in PDORn is set to the inverse of its existing logic state.</description>
                  <value>#1</value>
                </enumeratedValue>
              </enumeratedValues>
            </field>
          </fields>
        </register>
        <register>
          <name>PDIR</name>
          <description>Port Data Input Register</description>
          <addressOffset>0x10</addressOffset>
          <size>32</size>
          <access>read-only</access>
          <resetValue>0</resetValue>
          <resetMask>0xFFFFFFFF</resetMask>
          <fields>
            <field>
              <name>PDI</name>
              <description>Port Data Input</description>
              <bitOffset>0</bitOffset>
              <bitWidth>32</bitWidth>
              <access>read-only</access>
              <enumeratedValues>
                <enumeratedValue>
                  <name>0</name>
                  <description>Pin logic level is logic 0, or is not configured for use by digital function.</description>
                  <value>#0</value>
                </enumeratedValue>
                <enumeratedValue>
                  <name>1</name>
                  <description>Pin logic level is logic 1.</description>
                  <value>#1</value>
                </enumeratedValue>
              </enumeratedValues>
            </field>
          </fields>
        </register>
        <register>
          <name>PDDR</name>
          <description>Port Data Direction Register</description>
          <addressOffset>0x14</addressOffset>
          <size>32</size>
          <access>read-write</access>
          <resetValue>0</resetValue>
          <resetMask>0xFFFFFFFF</resetMask>
          <fields>
            <field>
              <name>PDD</name>
              <description>Port Data Direction</description>
              <bitOffset>0</bitOffset>
              <bitWidth>32</bitWidth>
              <access>read-write</access>
              <enumeratedValues>
                <enumeratedValue>
                  <name>0</name>
                  <description>Pin is configured as general-purpose input, for the GPIO function.</description>
                  <value>#0</value>
                </enumeratedValue>
                <enumeratedValue>
                  <name>1</name>
                  <description>Pin is configured as general-purpose output, for the GPIO function.</description>
                  <value>#1</value>
                </enumeratedValue>
              </enumeratedValues>
            </field>
          </fields>
        </register>
      </registers>
    </peripheral>
    <peripheral>
      <name>FGPIOB</name>
      <description>General Purpose Input/Output</description>
      <groupName>FGPIO</groupName>
      <prependToName>FGPIOB_</prependToName>
      <baseAddress>0xF8000040</baseAddress>
      <addressBlock>
        <offset>0</offset>
        <size>0x18</size>
        <usage>registers</usage>
      </addressBlock>
      <registers>
        <register>
          <name>PDOR</name>
          <description>Port Data Output Register</description>
          <addressOffset>0</addressOffset>
          <size>32</size>
          <access>read-write</access>
          <resetValue>0</resetValue>
          <resetMask>0xFFFFFFFF</resetMask>
          <fields>
            <field>
              <name>PDO</name>
              <description>Port Data Output</description>
              <bitOffset>0</bitOffset>
              <bitWidth>32</bitWidth>
              <access>read-write</access>
              <enumeratedValues>
                <enumeratedValue>
                  <name>0</name>
                  <description>Logic level 0 is driven on pin, provided pin is configured for general-purpose output.</description>
                  <value>#0</value>
                </enumeratedValue>
                <enumeratedValue>
                  <name>1</name>
                  <description>Logic level 1 is driven on pin, provided pin is configured for general-purpose output.</description>
                  <value>#1</value>
                </enumeratedValue>
              </enumeratedValues>
            </field>
          </fields>
        </register>
        <register>
          <name>PSOR</name>
          <description>Port Set Output Register</description>
          <addressOffset>0x4</addressOffset>
          <size>32</size>
          <access>write-only</access>
          <resetValue>0</resetValue>
          <resetMask>0xFFFFFFFF</resetMask>
          <fields>
            <field>
              <name>PTSO</name>
              <description>Port Set Output</description>
              <bitOffset>0</bitOffset>
              <bitWidth>32</bitWidth>
              <access>write-only</access>
              <enumeratedValues>
                <enumeratedValue>
                  <name>0</name>
                  <description>Corresponding bit in PDORn does not change.</description>
                  <value>#0</value>
                </enumeratedValue>
                <enumeratedValue>
                  <name>1</name>
                  <description>Corresponding bit in PDORn is set to logic 1.</description>
                  <value>#1</value>
                </enumeratedValue>
              </enumeratedValues>
            </field>
          </fields>
        </register>
        <register>
          <name>PCOR</name>
          <description>Port Clear Output Register</description>
          <addressOffset>0x8</addressOffset>
          <size>32</size>
          <access>write-only</access>
          <resetValue>0</resetValue>
          <resetMask>0xFFFFFFFF</resetMask>
          <fields>
            <field>
              <name>PTCO</name>
              <description>Port Clear Output</description>
              <bitOffset>0</bitOffset>
              <bitWidth>32</bitWidth>
              <access>write-only</access>
              <enumeratedValues>
                <enumeratedValue>
                  <name>0</name>
                  <description>Corresponding bit in PDORn does not change.</description>
                  <value>#0</value>
                </enumeratedValue>
                <enumeratedValue>
                  <name>1</name>
                  <description>Corresponding bit in PDORn is cleared to logic 0.</description>
                  <value>#1</value>
                </enumeratedValue>
              </enumeratedValues>
            </field>
          </fields>
        </register>
        <register>
          <name>PTOR</name>
          <description>Port Toggle Output Register</description>
          <addressOffset>0xC</addressOffset>
          <size>32</size>
          <access>write-only</access>
          <resetValue>0</resetValue>
          <resetMask>0xFFFFFFFF</resetMask>
          <fields>
            <field>
              <name>PTTO</name>
              <description>Port Toggle Output</description>
              <bitOffset>0</bitOffset>
              <bitWidth>32</bitWidth>
              <access>write-only</access>
              <enumeratedValues>
                <enumeratedValue>
                  <name>0</name>
                  <description>Corresponding bit in PDORn does not change.</description>
                  <value>#0</value>
                </enumeratedValue>
                <enumeratedValue>
                  <name>1</name>
                  <description>Corresponding bit in PDORn is set to the inverse of its existing logic state.</description>
                  <value>#1</value>
                </enumeratedValue>
              </enumeratedValues>
            </field>
          </fields>
        </register>
        <register>
          <name>PDIR</name>
          <description>Port Data Input Register</description>
          <addressOffset>0x10</addressOffset>
          <size>32</size>
          <access>read-only</access>
          <resetValue>0</resetValue>
          <resetMask>0xFFFFFFFF</resetMask>
          <fields>
            <field>
              <name>PDI</name>
              <description>Port Data Input</description>
              <bitOffset>0</bitOffset>
              <bitWidth>32</bitWidth>
              <access>read-only</access>
              <enumeratedValues>
                <enumeratedValue>
                  <name>0</name>
                  <description>Pin logic level is logic 0, or is not configured for use by digital function.</description>
                  <value>#0</value>
                </enumeratedValue>
                <enumeratedValue>
                  <name>1</name>
                  <description>Pin logic level is logic 1.</description>
                  <value>#1</value>
                </enumeratedValue>
              </enumeratedValues>
            </field>
          </fields>
        </register>
        <register>
          <name>PDDR</name>
          <description>Port Data Direction Register</description>
          <addressOffset>0x14</addressOffset>
          <size>32</size>
          <access>read-write</access>
          <resetValue>0</resetValue>
          <resetMask>0xFFFFFFFF</resetMask>
          <fields>
            <field>
              <name>PDD</name>
              <description>Port Data Direction</description>
              <bitOffset>0</bitOffset>
              <bitWidth>32</bitWidth>
              <access>read-write</access>
              <enumeratedValues>
                <enumeratedValue>
                  <name>0</name>
                  <description>Pin is configured as general-purpose input, for the GPIO function.</description>
                  <value>#0</value>
                </enumeratedValue>
                <enumeratedValue>
                  <name>1</name>
                  <description>Pin is configured as general-purpose output, for the GPIO function.</description>
                  <value>#1</value>
                </enumeratedValue>
              </enumeratedValues>
            </field>
          </fields>
        </register>
      </registers>
    </peripheral>
    <peripheral>
      <name>FGPIOC</name>
      <description>General Purpose Input/Output</description>
      <groupName>FGPIO</groupName>
      <prependToName>FGPIOC_</prependToName>
      <baseAddress>0xF8000080</baseAddress>
      <addressBlock>
        <offset>0</offset>
        <size>0x18</size>
        <usage>registers</usage>
      </addressBlock>
      <registers>
        <register>
          <name>PDOR</name>
          <description>Port Data Output Register</description>
          <addressOffset>0</addressOffset>
          <size>32</size>
          <access>read-write</access>
          <resetValue>0</resetValue>
          <resetMask>0xFFFFFFFF</resetMask>
          <fields>
            <field>
              <name>PDO</name>
              <description>Port Data Output</description>
              <bitOffset>0</bitOffset>
              <bitWidth>32</bitWidth>
              <access>read-write</access>
              <enumeratedValues>
                <enumeratedValue>
                  <name>0</name>
                  <description>Logic level 0 is driven on pin, provided pin is configured for general-purpose output.</description>
                  <value>#0</value>
                </enumeratedValue>
                <enumeratedValue>
                  <name>1</name>
                  <description>Logic level 1 is driven on pin, provided pin is configured for general-purpose output.</description>
                  <value>#1</value>
                </enumeratedValue>
              </enumeratedValues>
            </field>
          </fields>
        </register>
        <register>
          <name>PSOR</name>
          <description>Port Set Output Register</description>
          <addressOffset>0x4</addressOffset>
          <size>32</size>
          <access>write-only</access>
          <resetValue>0</resetValue>
          <resetMask>0xFFFFFFFF</resetMask>
          <fields>
            <field>
              <name>PTSO</name>
              <description>Port Set Output</description>
              <bitOffset>0</bitOffset>
              <bitWidth>32</bitWidth>
              <access>write-only</access>
              <enumeratedValues>
                <enumeratedValue>
                  <name>0</name>
                  <description>Corresponding bit in PDORn does not change.</description>
                  <value>#0</value>
                </enumeratedValue>
                <enumeratedValue>
                  <name>1</name>
                  <description>Corresponding bit in PDORn is set to logic 1.</description>
                  <value>#1</value>
                </enumeratedValue>
              </enumeratedValues>
            </field>
          </fields>
        </register>
        <register>
          <name>PCOR</name>
          <description>Port Clear Output Register</description>
          <addressOffset>0x8</addressOffset>
          <size>32</size>
          <access>write-only</access>
          <resetValue>0</resetValue>
          <resetMask>0xFFFFFFFF</resetMask>
          <fields>
            <field>
              <name>PTCO</name>
              <description>Port Clear Output</description>
              <bitOffset>0</bitOffset>
              <bitWidth>32</bitWidth>
              <access>write-only</access>
              <enumeratedValues>
                <enumeratedValue>
                  <name>0</name>
                  <description>Corresponding bit in PDORn does not change.</description>
                  <value>#0</value>
                </enumeratedValue>
                <enumeratedValue>
                  <name>1</name>
                  <description>Corresponding bit in PDORn is cleared to logic 0.</description>
                  <value>#1</value>
                </enumeratedValue>
              </enumeratedValues>
            </field>
          </fields>
        </register>
        <register>
          <name>PTOR</name>
          <description>Port Toggle Output Register</description>
          <addressOffset>0xC</addressOffset>
          <size>32</size>
          <access>write-only</access>
          <resetValue>0</resetValue>
          <resetMask>0xFFFFFFFF</resetMask>
          <fields>
            <field>
              <name>PTTO</name>
              <description>Port Toggle Output</description>
              <bitOffset>0</bitOffset>
              <bitWidth>32</bitWidth>
              <access>write-only</access>
              <enumeratedValues>
                <enumeratedValue>
                  <name>0</name>
                  <description>Corresponding bit in PDORn does not change.</description>
                  <value>#0</value>
                </enumeratedValue>
                <enumeratedValue>
                  <name>1</name>
                  <description>Corresponding bit in PDORn is set to the inverse of its existing logic state.</description>
                  <value>#1</value>
                </enumeratedValue>
              </enumeratedValues>
            </field>
          </fields>
        </register>
        <register>
          <name>PDIR</name>
          <description>Port Data Input Register</description>
          <addressOffset>0x10</addressOffset>
          <size>32</size>
          <access>read-only</access>
          <resetValue>0</resetValue>
          <resetMask>0xFFFFFFFF</resetMask>
          <fields>
            <field>
              <name>PDI</name>
              <description>Port Data Input</description>
              <bitOffset>0</bitOffset>
              <bitWidth>32</bitWidth>
              <access>read-only</access>
              <enumeratedValues>
                <enumeratedValue>
                  <name>0</name>
                  <description>Pin logic level is logic 0, or is not configured for use by digital function.</description>
                  <value>#0</value>
                </enumeratedValue>
                <enumeratedValue>
                  <name>1</name>
                  <description>Pin logic level is logic 1.</description>
                  <value>#1</value>
                </enumeratedValue>
              </enumeratedValues>
            </field>
          </fields>
        </register>
        <register>
          <name>PDDR</name>
          <description>Port Data Direction Register</description>
          <addressOffset>0x14</addressOffset>
          <size>32</size>
          <access>read-write</access>
          <resetValue>0</resetValue>
          <resetMask>0xFFFFFFFF</resetMask>
          <fields>
            <field>
              <name>PDD</name>
              <description>Port Data Direction</description>
              <bitOffset>0</bitOffset>
              <bitWidth>32</bitWidth>
              <access>read-write</access>
              <enumeratedValues>
                <enumeratedValue>
                  <name>0</name>
                  <description>Pin is configured as general-purpose input, for the GPIO function.</description>
                  <value>#0</value>
                </enumeratedValue>
                <enumeratedValue>
                  <name>1</name>
                  <description>Pin is configured as general-purpose output, for the GPIO function.</description>
                  <value>#1</value>
                </enumeratedValue>
              </enumeratedValues>
            </field>
          </fields>
        </register>
      </registers>
    </peripheral>
    <peripheral>
      <name>FGPIOD</name>
      <description>General Purpose Input/Output</description>
      <groupName>FGPIO</groupName>
      <prependToName>FGPIOD_</prependToName>
      <baseAddress>0xF80000C0</baseAddress>
      <addressBlock>
        <offset>0</offset>
        <size>0x18</size>
        <usage>registers</usage>
      </addressBlock>
      <registers>
        <register>
          <name>PDOR</name>
          <description>Port Data Output Register</description>
          <addressOffset>0</addressOffset>
          <size>32</size>
          <access>read-write</access>
          <resetValue>0</resetValue>
          <resetMask>0xFFFFFFFF</resetMask>
          <fields>
            <field>
              <name>PDO</name>
              <description>Port Data Output</description>
              <bitOffset>0</bitOffset>
              <bitWidth>32</bitWidth>
              <access>read-write</access>
              <enumeratedValues>
                <enumeratedValue>
                  <name>0</name>
                  <description>Logic level 0 is driven on pin, provided pin is configured for general-purpose output.</description>
                  <value>#0</value>
                </enumeratedValue>
                <enumeratedValue>
                  <name>1</name>
                  <description>Logic level 1 is driven on pin, provided pin is configured for general-purpose output.</description>
                  <value>#1</value>
                </enumeratedValue>
              </enumeratedValues>
            </field>
          </fields>
        </register>
        <register>
          <name>PSOR</name>
          <description>Port Set Output Register</description>
          <addressOffset>0x4</addressOffset>
          <size>32</size>
          <access>write-only</access>
          <resetValue>0</resetValue>
          <resetMask>0xFFFFFFFF</resetMask>
          <fields>
            <field>
              <name>PTSO</name>
              <description>Port Set Output</description>
              <bitOffset>0</bitOffset>
              <bitWidth>32</bitWidth>
              <access>write-only</access>
              <enumeratedValues>
                <enumeratedValue>
                  <name>0</name>
                  <description>Corresponding bit in PDORn does not change.</description>
                  <value>#0</value>
                </enumeratedValue>
                <enumeratedValue>
                  <name>1</name>
                  <description>Corresponding bit in PDORn is set to logic 1.</description>
                  <value>#1</value>
                </enumeratedValue>
              </enumeratedValues>
            </field>
          </fields>
        </register>
        <register>
          <name>PCOR</name>
          <description>Port Clear Output Register</description>
          <addressOffset>0x8</addressOffset>
          <size>32</size>
          <access>write-only</access>
          <resetValue>0</resetValue>
          <resetMask>0xFFFFFFFF</resetMask>
          <fields>
            <field>
              <name>PTCO</name>
              <description>Port Clear Output</description>
              <bitOffset>0</bitOffset>
              <bitWidth>32</bitWidth>
              <access>write-only</access>
              <enumeratedValues>
                <enumeratedValue>
                  <name>0</name>
                  <description>Corresponding bit in PDORn does not change.</description>
                  <value>#0</value>
                </enumeratedValue>
                <enumeratedValue>
                  <name>1</name>
                  <description>Corresponding bit in PDORn is cleared to logic 0.</description>
                  <value>#1</value>
                </enumeratedValue>
              </enumeratedValues>
            </field>
          </fields>
        </register>
        <register>
          <name>PTOR</name>
          <description>Port Toggle Output Register</description>
          <addressOffset>0xC</addressOffset>
          <size>32</size>
          <access>write-only</access>
          <resetValue>0</resetValue>
          <resetMask>0xFFFFFFFF</resetMask>
          <fields>
            <field>
              <name>PTTO</name>
              <description>Port Toggle Output</description>
              <bitOffset>0</bitOffset>
              <bitWidth>32</bitWidth>
              <access>write-only</access>
              <enumeratedValues>
                <enumeratedValue>
                  <name>0</name>
                  <description>Corresponding bit in PDORn does not change.</description>
                  <value>#0</value>
                </enumeratedValue>
                <enumeratedValue>
                  <name>1</name>
                  <description>Corresponding bit in PDORn is set to the inverse of its existing logic state.</description>
                  <value>#1</value>
                </enumeratedValue>
              </enumeratedValues>
            </field>
          </fields>
        </register>
        <register>
          <name>PDIR</name>
          <description>Port Data Input Register</description>
          <addressOffset>0x10</addressOffset>
          <size>32</size>
          <access>read-only</access>
          <resetValue>0</resetValue>
          <resetMask>0xFFFFFFFF</resetMask>
          <fields>
            <field>
              <name>PDI</name>
              <description>Port Data Input</description>
              <bitOffset>0</bitOffset>
              <bitWidth>32</bitWidth>
              <access>read-only</access>
              <enumeratedValues>
                <enumeratedValue>
                  <name>0</name>
                  <description>Pin logic level is logic 0, or is not configured for use by digital function.</description>
                  <value>#0</value>
                </enumeratedValue>
                <enumeratedValue>
                  <name>1</name>
                  <description>Pin logic level is logic 1.</description>
                  <value>#1</value>
                </enumeratedValue>
              </enumeratedValues>
            </field>
          </fields>
        </register>
        <register>
          <name>PDDR</name>
          <description>Port Data Direction Register</description>
          <addressOffset>0x14</addressOffset>
          <size>32</size>
          <access>read-write</access>
          <resetValue>0</resetValue>
          <resetMask>0xFFFFFFFF</resetMask>
          <fields>
            <field>
              <name>PDD</name>
              <description>Port Data Direction</description>
              <bitOffset>0</bitOffset>
              <bitWidth>32</bitWidth>
              <access>read-write</access>
              <enumeratedValues>
                <enumeratedValue>
                  <name>0</name>
                  <description>Pin is configured as general-purpose input, for the GPIO function.</description>
                  <value>#0</value>
                </enumeratedValue>
                <enumeratedValue>
                  <name>1</name>
                  <description>Pin is configured as general-purpose output, for the GPIO function.</description>
                  <value>#1</value>
                </enumeratedValue>
              </enumeratedValues>
            </field>
          </fields>
        </register>
      </registers>
    </peripheral>
    <peripheral>
      <name>FGPIOE</name>
      <description>General Purpose Input/Output</description>
      <groupName>FGPIO</groupName>
      <prependToName>FGPIOE_</prependToName>
      <baseAddress>0xF8000100</baseAddress>
      <addressBlock>
        <offset>0</offset>
        <size>0x18</size>
        <usage>registers</usage>
      </addressBlock>
      <registers>
        <register>
          <name>PDOR</name>
          <description>Port Data Output Register</description>
          <addressOffset>0</addressOffset>
          <size>32</size>
          <access>read-write</access>
          <resetValue>0</resetValue>
          <resetMask>0xFFFFFFFF</resetMask>
          <fields>
            <field>
              <name>PDO</name>
              <description>Port Data Output</description>
              <bitOffset>0</bitOffset>
              <bitWidth>32</bitWidth>
              <access>read-write</access>
              <enumeratedValues>
                <enumeratedValue>
                  <name>0</name>
                  <description>Logic level 0 is driven on pin, provided pin is configured for general-purpose output.</description>
                  <value>#0</value>
                </enumeratedValue>
                <enumeratedValue>
                  <name>1</name>
                  <description>Logic level 1 is driven on pin, provided pin is configured for general-purpose output.</description>
                  <value>#1</value>
                </enumeratedValue>
              </enumeratedValues>
            </field>
          </fields>
        </register>
        <register>
          <name>PSOR</name>
          <description>Port Set Output Register</description>
          <addressOffset>0x4</addressOffset>
          <size>32</size>
          <access>write-only</access>
          <resetValue>0</resetValue>
          <resetMask>0xFFFFFFFF</resetMask>
          <fields>
            <field>
              <name>PTSO</name>
              <description>Port Set Output</description>
              <bitOffset>0</bitOffset>
              <bitWidth>32</bitWidth>
              <access>write-only</access>
              <enumeratedValues>
                <enumeratedValue>
                  <name>0</name>
                  <description>Corresponding bit in PDORn does not change.</description>
                  <value>#0</value>
                </enumeratedValue>
                <enumeratedValue>
                  <name>1</name>
                  <description>Corresponding bit in PDORn is set to logic 1.</description>
                  <value>#1</value>
                </enumeratedValue>
              </enumeratedValues>
            </field>
          </fields>
        </register>
        <register>
          <name>PCOR</name>
          <description>Port Clear Output Register</description>
          <addressOffset>0x8</addressOffset>
          <size>32</size>
          <access>write-only</access>
          <resetValue>0</resetValue>
          <resetMask>0xFFFFFFFF</resetMask>
          <fields>
            <field>
              <name>PTCO</name>
              <description>Port Clear Output</description>
              <bitOffset>0</bitOffset>
              <bitWidth>32</bitWidth>
              <access>write-only</access>
              <enumeratedValues>
                <enumeratedValue>
                  <name>0</name>
                  <description>Corresponding bit in PDORn does not change.</description>
                  <value>#0</value>
                </enumeratedValue>
                <enumeratedValue>
                  <name>1</name>
                  <description>Corresponding bit in PDORn is cleared to logic 0.</description>
                  <value>#1</value>
                </enumeratedValue>
              </enumeratedValues>
            </field>
          </fields>
        </register>
        <register>
          <name>PTOR</name>
          <description>Port Toggle Output Register</description>
          <addressOffset>0xC</addressOffset>
          <size>32</size>
          <access>write-only</access>
          <resetValue>0</resetValue>
          <resetMask>0xFFFFFFFF</resetMask>
          <fields>
            <field>
              <name>PTTO</name>
              <description>Port Toggle Output</description>
              <bitOffset>0</bitOffset>
              <bitWidth>32</bitWidth>
              <access>write-only</access>
              <enumeratedValues>
                <enumeratedValue>
                  <name>0</name>
                  <description>Corresponding bit in PDORn does not change.</description>
                  <value>#0</value>
                </enumeratedValue>
                <enumeratedValue>
                  <name>1</name>
                  <description>Corresponding bit in PDORn is set to the inverse of its existing logic state.</description>
                  <value>#1</value>
                </enumeratedValue>
              </enumeratedValues>
            </field>
          </fields>
        </register>
        <register>
          <name>PDIR</name>
          <description>Port Data Input Register</description>
          <addressOffset>0x10</addressOffset>
          <size>32</size>
          <access>read-only</access>
          <resetValue>0</resetValue>
          <resetMask>0xFFFFFFFF</resetMask>
          <fields>
            <field>
              <name>PDI</name>
              <description>Port Data Input</description>
              <bitOffset>0</bitOffset>
              <bitWidth>32</bitWidth>
              <access>read-only</access>
              <enumeratedValues>
                <enumeratedValue>
                  <name>0</name>
                  <description>Pin logic level is logic 0, or is not configured for use by digital function.</description>
                  <value>#0</value>
                </enumeratedValue>
                <enumeratedValue>
                  <name>1</name>
                  <description>Pin logic level is logic 1.</description>
                  <value>#1</value>
                </enumeratedValue>
              </enumeratedValues>
            </field>
          </fields>
        </register>
        <register>
          <name>PDDR</name>
          <description>Port Data Direction Register</description>
          <addressOffset>0x14</addressOffset>
          <size>32</size>
          <access>read-write</access>
          <resetValue>0</resetValue>
          <resetMask>0xFFFFFFFF</resetMask>
          <fields>
            <field>
              <name>PDD</name>
              <description>Port Data Direction</description>
              <bitOffset>0</bitOffset>
              <bitWidth>32</bitWidth>
              <access>read-write</access>
              <enumeratedValues>
                <enumeratedValue>
                  <name>0</name>
                  <description>Pin is configured as general-purpose input, for the GPIO function.</description>
                  <value>#0</value>
                </enumeratedValue>
                <enumeratedValue>
                  <name>1</name>
                  <description>Pin is configured as general-purpose output, for the GPIO function.</description>
                  <value>#1</value>
                </enumeratedValue>
              </enumeratedValues>
            </field>
          </fields>
        </register>
      </registers>
    </peripheral>
  </peripherals>
</device>
